###############################################################
#  Generated by:      Cadence Innovus 21.16-s078_1
#  OS:                Linux x86_64(Host ID iron-10)
#  Generated on:      Fri Feb 27 18:19:35 2026
#  Design:            conv
#  Command:           write_lef_abstract -specifyTopLayer 6 -PGPinLayers {5 6} -noCutObs -stripePin results/conv.lef
###############################################################

VERSION 5.8 ;

BUSBITCHARS "[]" ;
DIVIDERCHAR "/" ;

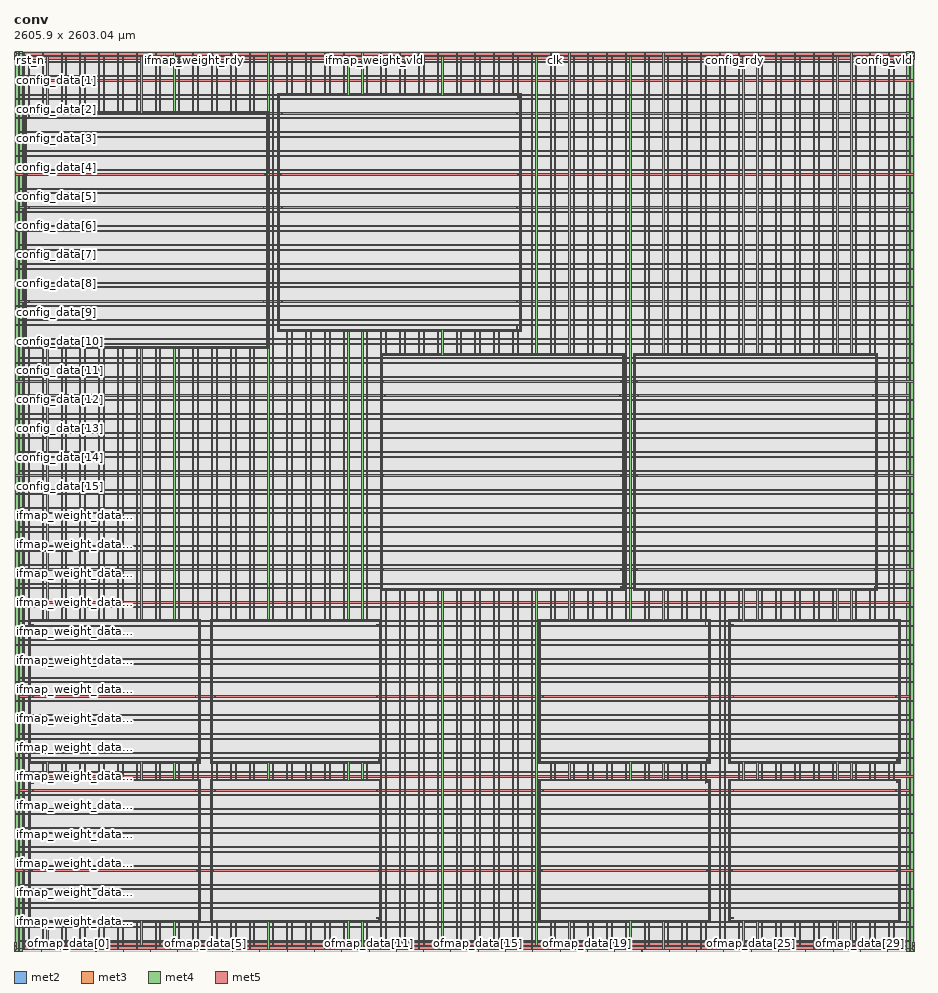
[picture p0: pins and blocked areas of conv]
MACRO conv
  CLASS BLOCK ;
  SIZE 2605.900000 BY 2603.040000 ;
  FOREIGN conv 0.000000 0.000000 ;
  ORIGIN 0 0 ;
  SYMMETRY X Y R90 ;
  PIN clk
    DIRECTION INPUT ;
    USE SIGNAL ;
    ANTENNAPARTIALMETALAREA 6.5113 LAYER met2  ;
    ANTENNAPARTIALMETALSIDEAREA 32.4485 LAYER met2  ;
    ANTENNAMODEL OXIDE1 ;
    ANTENNAGATEAREA 0.576 LAYER met2  ;
    ANTENNAMAXAREACAR 12.7497 LAYER met2  ;
    ANTENNAMAXSIDEAREACAR 61.5451 LAYER met2  ;
    ANTENNAMAXCUTCAR 0.0892361 LAYER via2  ;
    PORT
      LAYER met2 ;
        RECT 1563.240000 2602.555000 1563.380000 2603.040000 ;
    END
  END clk
  PIN rst_n
    DIRECTION INPUT ;
    USE SIGNAL ;
    ANTENNAPARTIALMETALAREA 9.5841 LAYER met2  ;
    ANTENNAPARTIALMETALSIDEAREA 47.6945 LAYER met2  ;
    ANTENNAMODEL OXIDE1 ;
    ANTENNAGATEAREA 0.576 LAYER met2  ;
    ANTENNAMAXAREACAR 34.4979 LAYER met2  ;
    ANTENNAMAXSIDEAREACAR 170.082 LAYER met2  ;
    ANTENNAMAXCUTCAR 0.0892361 LAYER via2  ;
    PORT
      LAYER met2 ;
        RECT 0.160000 2602.555000 0.300000 2603.040000 ;
    END
  END rst_n
  PIN ifmap_weight_data[16]
    DIRECTION INPUT ;
    USE SIGNAL ;
  END ifmap_weight_data[16]
  PIN ifmap_weight_data[15]
    DIRECTION INPUT ;
    USE SIGNAL ;
    ANTENNAPARTIALMETALAREA 6.3264 LAYER met3  ;
    ANTENNAPARTIALMETALSIDEAREA 33.736 LAYER met3  ;
    ANTENNAMODEL OXIDE1 ;
    ANTENNAGATEAREA 0.1965 LAYER met3  ;
    ANTENNAMAXAREACAR 37.8972 LAYER met3  ;
    ANTENNAMAXSIDEAREACAR 194.982 LAYER met3  ;
    ANTENNAMAXCUTCAR 0.46514 LAYER via3  ;
    PORT
      LAYER met3 ;
        RECT 0.000000 0.520000 0.800000 0.820000 ;
    END
  END ifmap_weight_data[15]
  PIN ifmap_weight_data[14]
    DIRECTION INPUT ;
    USE SIGNAL ;
    ANTENNAPARTIALMETALAREA 0.6954 LAYER met3  ;
    ANTENNAPARTIALMETALSIDEAREA 4.152 LAYER met3  ;
    ANTENNAPARTIALCUTAREA 0.04 LAYER via3  ;
    ANTENNADIFFAREA 0.4347 LAYER met4  ;
    ANTENNAPARTIALMETALAREA 6.1578 LAYER met4  ;
    ANTENNAPARTIALMETALSIDEAREA 33.312 LAYER met4  ;
    ANTENNAMODEL OXIDE1 ;
    ANTENNAGATEAREA 0.6312 LAYER met4  ;
    ANTENNAMAXAREACAR 117.866 LAYER met4  ;
    ANTENNAMAXSIDEAREACAR 579.27 LAYER met4  ;
    ANTENNAMAXCUTCAR 0.208175 LAYER via4  ;
    PORT
      LAYER met3 ;
        RECT 0.000000 84.090000 0.800000 84.390000 ;
    END
  END ifmap_weight_data[14]
  PIN ifmap_weight_data[13]
    DIRECTION INPUT ;
    USE SIGNAL ;
    ANTENNAPARTIALMETALAREA 6.6504 LAYER met3  ;
    ANTENNAPARTIALMETALSIDEAREA 35.464 LAYER met3  ;
    ANTENNAMODEL OXIDE1 ;
    ANTENNAGATEAREA 0.1965 LAYER met3  ;
    ANTENNAMAXAREACAR 59.1237 LAYER met3  ;
    ANTENNAMAXSIDEAREACAR 298.326 LAYER met3  ;
    ANTENNAMAXCUTCAR 0.46514 LAYER via3  ;
    PORT
      LAYER met3 ;
        RECT 0.000000 168.270000 0.800000 168.570000 ;
    END
  END ifmap_weight_data[13]
  PIN ifmap_weight_data[12]
    DIRECTION INPUT ;
    USE SIGNAL ;
    ANTENNAPARTIALMETALAREA 0.8644 LAYER met3  ;
    ANTENNAPARTIALMETALSIDEAREA 5.072 LAYER met3  ;
    ANTENNAPARTIALCUTAREA 0.04 LAYER via3  ;
    ANTENNAPARTIALMETALAREA 3.2298 LAYER met4  ;
    ANTENNAPARTIALMETALSIDEAREA 17.696 LAYER met4  ;
    ANTENNAMODEL OXIDE1 ;
    ANTENNAGATEAREA 0.498 LAYER met4  ;
    ANTENNAMAXAREACAR 21.4641 LAYER met4  ;
    ANTENNAMAXSIDEAREACAR 101.959 LAYER met4  ;
    ANTENNAMAXCUTCAR 0.435188 LAYER via4  ;
    PORT
      LAYER met3 ;
        RECT 0.000000 251.840000 0.800000 252.140000 ;
    END
  END ifmap_weight_data[12]
  PIN ifmap_weight_data[11]
    DIRECTION INPUT ;
    USE SIGNAL ;
    ANTENNADIFFAREA 0.4347 LAYER met3  ;
    ANTENNAPARTIALMETALAREA 6.0984 LAYER met3  ;
    ANTENNAPARTIALMETALSIDEAREA 32.52 LAYER met3  ;
    ANTENNAMODEL OXIDE1 ;
    ANTENNAGATEAREA 0.9327 LAYER met3  ;
    ANTENNAMAXAREACAR 119.127 LAYER met3  ;
    ANTENNAMAXSIDEAREACAR 587.966 LAYER met3  ;
    ANTENNAMAXCUTCAR 0.393219 LAYER via3  ;
    PORT
      LAYER met3 ;
        RECT 0.000000 336.020000 0.800000 336.320000 ;
    END
  END ifmap_weight_data[11]
  PIN ifmap_weight_data[10]
    DIRECTION INPUT ;
    USE SIGNAL ;
    ANTENNADIFFAREA 0.4347 LAYER met3  ;
    ANTENNAPARTIALMETALAREA 6.6504 LAYER met3  ;
    ANTENNAPARTIALMETALSIDEAREA 35.464 LAYER met3  ;
    ANTENNAMODEL OXIDE1 ;
    ANTENNAGATEAREA 0.9327 LAYER met3  ;
    ANTENNAMAXAREACAR 107.73 LAYER met3  ;
    ANTENNAMAXSIDEAREACAR 522.98 LAYER met3  ;
    ANTENNAMAXCUTCAR 0.337782 LAYER via3  ;
    PORT
      LAYER met3 ;
        RECT 0.000000 420.200000 0.800000 420.500000 ;
    END
  END ifmap_weight_data[10]
  PIN ifmap_weight_data[9]
    DIRECTION INPUT ;
    USE SIGNAL ;
    ANTENNADIFFAREA 0.4347 LAYER met3  ;
    ANTENNAPARTIALMETALAREA 7.0644 LAYER met3  ;
    ANTENNAPARTIALMETALSIDEAREA 37.672 LAYER met3  ;
    ANTENNAMODEL OXIDE1 ;
    ANTENNAGATEAREA 0.9327 LAYER met3  ;
    ANTENNAMAXAREACAR 92.4371 LAYER met3  ;
    ANTENNAMAXSIDEAREACAR 462.152 LAYER met3  ;
    ANTENNAMAXCUTCAR 0.450823 LAYER via3  ;
    PORT
      LAYER met3 ;
        RECT 0.000000 503.770000 0.800000 504.070000 ;
    END
  END ifmap_weight_data[9]
  PIN ifmap_weight_data[8]
    DIRECTION INPUT ;
    USE SIGNAL ;
    ANTENNAPARTIALMETALAREA 0.5574 LAYER met3  ;
    ANTENNAPARTIALMETALSIDEAREA 3.416 LAYER met3  ;
    ANTENNAPARTIALCUTAREA 0.04 LAYER via3  ;
    ANTENNAPARTIALMETALAREA 4.1448 LAYER met4  ;
    ANTENNAPARTIALMETALSIDEAREA 22.576 LAYER met4  ;
    ANTENNAMODEL OXIDE1 ;
    ANTENNAGATEAREA 0.498 LAYER met4  ;
    ANTENNAMAXAREACAR 34.5191 LAYER met4  ;
    ANTENNAMAXSIDEAREACAR 166.018 LAYER met4  ;
    ANTENNAMAXCUTCAR 0.74715 LAYER via4  ;
    PORT
      LAYER met3 ;
        RECT 0.000000 587.950000 0.800000 588.250000 ;
    END
  END ifmap_weight_data[8]
  PIN ifmap_weight_data[7]
    DIRECTION INPUT ;
    USE SIGNAL ;
    ANTENNAPARTIALMETALAREA 8.0053 LAYER met3  ;
    ANTENNAPARTIALMETALSIDEAREA 43.16 LAYER met3  ;
    ANTENNAPARTIALCUTAREA 0.04 LAYER via3  ;
    ANTENNAPARTIALMETALAREA 4.3518 LAYER met4  ;
    ANTENNAPARTIALMETALSIDEAREA 23.68 LAYER met4  ;
    ANTENNAMODEL OXIDE1 ;
    ANTENNAGATEAREA 0.498 LAYER met4  ;
    ANTENNAMAXAREACAR 36.3557 LAYER met4  ;
    ANTENNAMAXSIDEAREACAR 177.137 LAYER met4  ;
    ANTENNAMAXCUTCAR 0.435188 LAYER via4  ;
    PORT
      LAYER met3 ;
        RECT 0.000000 671.520000 0.800000 671.820000 ;
    END
  END ifmap_weight_data[7]
  PIN ifmap_weight_data[6]
    DIRECTION INPUT ;
    USE SIGNAL ;
    ANTENNAPARTIALMETALAREA 0.8544 LAYER met3  ;
    ANTENNAPARTIALMETALSIDEAREA 4.552 LAYER met3  ;
    ANTENNAMODEL OXIDE1 ;
    ANTENNAGATEAREA 0.498 LAYER met3  ;
    ANTENNAMAXAREACAR 110.536 LAYER met3  ;
    ANTENNAMAXSIDEAREACAR 542.113 LAYER met3  ;
    ANTENNAMAXCUTCAR 0.666829 LAYER via3  ;
    PORT
      LAYER met3 ;
        RECT 0.000000 755.700000 0.800000 756.000000 ;
    END
  END ifmap_weight_data[6]
  PIN ifmap_weight_data[5]
    DIRECTION INPUT ;
    USE SIGNAL ;
    ANTENNAPARTIALMETALAREA 13.596 LAYER met3  ;
    ANTENNAPARTIALMETALSIDEAREA 73.448 LAYER met3  ;
    ANTENNAMODEL OXIDE1 ;
    ANTENNAGATEAREA 0.498 LAYER met3  ;
    ANTENNAMAXAREACAR 51.1759 LAYER met3  ;
    ANTENNAMAXSIDEAREACAR 255.575 LAYER met3  ;
    ANTENNAMAXCUTCAR 0.801562 LAYER via3  ;
    PORT
      LAYER met3 ;
        RECT 0.000000 839.880000 0.800000 840.180000 ;
    END
  END ifmap_weight_data[5]
  PIN ifmap_weight_data[4]
    DIRECTION INPUT ;
    USE SIGNAL ;
    ANTENNAPARTIALMETALAREA 13.5504 LAYER met3  ;
    ANTENNAPARTIALMETALSIDEAREA 72.264 LAYER met3  ;
    ANTENNAMODEL OXIDE1 ;
    ANTENNAGATEAREA 0.498 LAYER met3  ;
    ANTENNAMAXAREACAR 65.7007 LAYER met3  ;
    ANTENNAMAXSIDEAREACAR 327.226 LAYER met3  ;
    ANTENNAMAXCUTCAR 0.488258 LAYER via3  ;
    PORT
      LAYER met3 ;
        RECT 0.000000 923.450000 0.800000 923.750000 ;
    END
  END ifmap_weight_data[4]
  PIN ifmap_weight_data[3]
    DIRECTION INPUT ;
    USE SIGNAL ;
    ANTENNAPARTIALMETALAREA 0.1644 LAYER met3  ;
    ANTENNAPARTIALMETALSIDEAREA 0.872 LAYER met3  ;
    ANTENNAMODEL OXIDE1 ;
    ANTENNAGATEAREA 0.498 LAYER met3  ;
    ANTENNAMAXAREACAR 35.9706 LAYER met3  ;
    ANTENNAMAXSIDEAREACAR 168.607 LAYER met3  ;
    ANTENNAMAXCUTCAR 0.666829 LAYER via3  ;
    PORT
      LAYER met3 ;
        RECT 0.000000 1007.630000 0.800000 1007.930000 ;
    END
  END ifmap_weight_data[3]
  PIN ifmap_weight_data[2]
    DIRECTION INPUT ;
    USE SIGNAL ;
    ANTENNAPARTIALMETALAREA 31.4904 LAYER met3  ;
    ANTENNAPARTIALMETALSIDEAREA 167.944 LAYER met3  ;
    ANTENNAMODEL OXIDE1 ;
    ANTENNAGATEAREA 0.498 LAYER met3  ;
    ANTENNAMAXAREACAR 88.3315 LAYER met3  ;
    ANTENNAMAXSIDEAREACAR 452.75 LAYER met3  ;
    ANTENNAMAXCUTCAR 0.398972 LAYER via3  ;
    PORT
      LAYER met3 ;
        RECT 0.000000 1091.200000 0.800000 1091.500000 ;
    END
  END ifmap_weight_data[2]
  PIN ifmap_weight_data[1]
    DIRECTION INPUT ;
    USE SIGNAL ;
    ANTENNAPARTIALMETALAREA 8.3064 LAYER met3  ;
    ANTENNAPARTIALMETALSIDEAREA 44.296 LAYER met3  ;
    ANTENNAMODEL OXIDE1 ;
    ANTENNAGATEAREA 0.498 LAYER met3  ;
    ANTENNAMAXAREACAR 75.0135 LAYER met3  ;
    ANTENNAMAXSIDEAREACAR 369.809 LAYER met3  ;
    ANTENNAMAXCUTCAR 0.666829 LAYER via3  ;
    PORT
      LAYER met3 ;
        RECT 0.000000 1175.380000 0.800000 1175.680000 ;
    END
  END ifmap_weight_data[1]
  PIN ifmap_weight_data[0]
    DIRECTION INPUT ;
    USE SIGNAL ;
    ANTENNAPARTIALMETALAREA 30.9384 LAYER met3  ;
    ANTENNAPARTIALMETALSIDEAREA 165 LAYER met3  ;
    ANTENNAMODEL OXIDE1 ;
    ANTENNAGATEAREA 0.498 LAYER met3  ;
    ANTENNAMAXAREACAR 142.031 LAYER met3  ;
    ANTENNAMAXSIDEAREACAR 720.859 LAYER met3  ;
    ANTENNAMAXCUTCAR 0.398972 LAYER via3  ;
    PORT
      LAYER met3 ;
        RECT 0.000000 1259.560000 0.800000 1259.860000 ;
    END
  END ifmap_weight_data[0]
  PIN ifmap_weight_rdy
    DIRECTION OUTPUT ;
    USE SIGNAL ;
    ANTENNADIFFAREA 0.43675 LAYER met2  ;
    ANTENNAPARTIALMETALAREA 32.4447 LAYER met2  ;
    ANTENNAPARTIALMETALSIDEAREA 161.997 LAYER met2  ;
    PORT
      LAYER met2 ;
        RECT 520.880000 2602.555000 521.020000 2603.040000 ;
    END
  END ifmap_weight_rdy
  PIN ifmap_weight_vld
    DIRECTION INPUT ;
    USE SIGNAL ;
    ANTENNAPARTIALMETALAREA 4.6507 LAYER met2  ;
    ANTENNAPARTIALMETALSIDEAREA 23.1455 LAYER met2  ;
    ANTENNAMODEL OXIDE1 ;
    ANTENNAGATEAREA 1.152 LAYER met2  ;
    ANTENNAMAXAREACAR 4.54191 LAYER met2  ;
    ANTENNAMAXSIDEAREACAR 20.8676 LAYER met2  ;
    ANTENNAMAXCUTCAR 0.0446181 LAYER via2  ;
    PORT
      LAYER met2 ;
        RECT 1042.060000 2602.555000 1042.200000 2603.040000 ;
    END
  END ifmap_weight_vld
  PIN ofmap_data[31]
    DIRECTION OUTPUT ;
    USE SIGNAL ;
    ANTENNADIFFAREA 0.3406 LAYER met2  ;
    ANTENNAPARTIALMETALAREA 10.1581 LAYER met2  ;
    ANTENNAPARTIALMETALSIDEAREA 50.5645 LAYER met2  ;
    PORT
      LAYER met2 ;
        RECT 2605.600000 0.000000 2605.740000 0.485000 ;
    END
  END ofmap_data[31]
  PIN ofmap_data[30]
    DIRECTION OUTPUT ;
    USE SIGNAL ;
    ANTENNADIFFAREA 0.3406 LAYER met2  ;
    ANTENNAPARTIALMETALAREA 10.2771 LAYER met2  ;
    ANTENNAPARTIALMETALSIDEAREA 51.1595 LAYER met2  ;
    PORT
      LAYER met2 ;
        RECT 2526.940000 0.000000 2527.080000 0.485000 ;
    END
  END ofmap_data[30]
  PIN ofmap_data[29]
    DIRECTION OUTPUT ;
    USE SIGNAL ;
    ANTENNADIFFAREA 0.3406 LAYER met2  ;
    ANTENNAPARTIALMETALAREA 10.2771 LAYER met2  ;
    ANTENNAPARTIALMETALSIDEAREA 51.1595 LAYER met2  ;
    PORT
      LAYER met2 ;
        RECT 2447.820000 0.000000 2447.960000 0.485000 ;
    END
  END ofmap_data[29]
  PIN ofmap_data[28]
    DIRECTION OUTPUT ;
    USE SIGNAL ;
    ANTENNADIFFAREA 0.3406 LAYER met2  ;
    ANTENNAPARTIALMETALAREA 5.4555 LAYER met2  ;
    ANTENNAPARTIALMETALSIDEAREA 27.0515 LAYER met2  ;
    PORT
      LAYER met2 ;
        RECT 2369.160000 0.000000 2369.300000 0.485000 ;
    END
  END ofmap_data[28]
  PIN ofmap_data[27]
    DIRECTION OUTPUT ;
    USE SIGNAL ;
    ANTENNADIFFAREA 0.3406 LAYER met2  ;
    ANTENNAPARTIALMETALAREA 7.9183 LAYER met2  ;
    ANTENNAPARTIALMETALSIDEAREA 39.4835 LAYER met2  ;
    PORT
      LAYER met2 ;
        RECT 2290.040000 0.000000 2290.180000 0.485000 ;
    END
  END ofmap_data[27]
  PIN ofmap_data[26]
    DIRECTION OUTPUT ;
    USE SIGNAL ;
    ANTENNADIFFAREA 0.3406 LAYER met2  ;
    ANTENNAPARTIALMETALAREA 4.2055 LAYER met2  ;
    ANTENNAPARTIALMETALSIDEAREA 20.9195 LAYER met2  ;
    PORT
      LAYER met2 ;
        RECT 2210.920000 0.000000 2211.060000 0.485000 ;
    END
  END ofmap_data[26]
  PIN ofmap_data[25]
    DIRECTION OUTPUT ;
    USE SIGNAL ;
    ANTENNADIFFAREA 0.3406 LAYER met2  ;
    ANTENNAPARTIALMETALAREA 4.8507 LAYER met2  ;
    ANTENNAPARTIALMETALSIDEAREA 24.0275 LAYER met2  ;
    PORT
      LAYER met2 ;
        RECT 2132.260000 0.000000 2132.400000 0.485000 ;
    END
  END ofmap_data[25]
  PIN ofmap_data[24]
    DIRECTION OUTPUT ;
    USE SIGNAL ;
    ANTENNADIFFAREA 0.3406 LAYER met2  ;
    ANTENNAPARTIALMETALAREA 4.1367 LAYER met2  ;
    ANTENNAPARTIALMETALSIDEAREA 20.4575 LAYER met2  ;
    PORT
      LAYER met2 ;
        RECT 2053.140000 0.000000 2053.280000 0.485000 ;
    END
  END ofmap_data[24]
  PIN ofmap_data[23]
    DIRECTION OUTPUT ;
    USE SIGNAL ;
    ANTENNADIFFAREA 0.3406 LAYER met2  ;
    ANTENNAPARTIALMETALAREA 8.5635 LAYER met2  ;
    ANTENNAPARTIALMETALSIDEAREA 42.5915 LAYER met2  ;
    PORT
      LAYER met2 ;
        RECT 1974.020000 0.000000 1974.160000 0.485000 ;
    END
  END ofmap_data[23]
  PIN ofmap_data[22]
    DIRECTION OUTPUT ;
    USE SIGNAL ;
    ANTENNADIFFAREA 0.3406 LAYER met2  ;
    ANTENNAPARTIALMETALAREA 10.2771 LAYER met2  ;
    ANTENNAPARTIALMETALSIDEAREA 51.1595 LAYER met2  ;
    PORT
      LAYER met2 ;
        RECT 1895.360000 0.000000 1895.500000 0.485000 ;
    END
  END ofmap_data[22]
  PIN ofmap_data[21]
    DIRECTION OUTPUT ;
    USE SIGNAL ;
    ANTENNADIFFAREA 0.3406 LAYER met2  ;
    ANTENNAPARTIALMETALAREA 11.4839 LAYER met2  ;
    ANTENNAPARTIALMETALSIDEAREA 57.1935 LAYER met2  ;
    PORT
      LAYER met2 ;
        RECT 1816.240000 0.000000 1816.380000 0.485000 ;
    END
  END ofmap_data[21]
  PIN ofmap_data[20]
    DIRECTION OUTPUT ;
    USE SIGNAL ;
    ANTENNADIFFAREA 0.429 LAYER met2  ;
    ANTENNAPARTIALMETALAREA 54.9119 LAYER met2  ;
    ANTENNAPARTIALMETALSIDEAREA 274.333 LAYER met2  ;
    PORT
      LAYER met2 ;
        RECT 1737.580000 0.000000 1737.720000 0.485000 ;
    END
  END ofmap_data[20]
  PIN ofmap_data[19]
    DIRECTION OUTPUT ;
    USE SIGNAL ;
    ANTENNADIFFAREA 0.429 LAYER met2  ;
    ANTENNAPARTIALMETALAREA 56.6871 LAYER met2  ;
    ANTENNAPARTIALMETALSIDEAREA 283.21 LAYER met2  ;
    PORT
      LAYER met2 ;
        RECT 1658.460000 0.000000 1658.600000 0.485000 ;
    END
  END ofmap_data[19]
  PIN ofmap_data[18]
    DIRECTION OUTPUT ;
    USE SIGNAL ;
    ANTENNADIFFAREA 0.429 LAYER met2  ;
    ANTENNAPARTIALMETALAREA 53.6407 LAYER met2  ;
    ANTENNAPARTIALMETALSIDEAREA 267.978 LAYER met2  ;
    PORT
      LAYER met2 ;
        RECT 1579.340000 0.000000 1579.480000 0.485000 ;
    END
  END ofmap_data[18]
  PIN ofmap_data[17]
    DIRECTION OUTPUT ;
    USE SIGNAL ;
    ANTENNADIFFAREA 0.429 LAYER met2  ;
    ANTENNAPARTIALMETALAREA 54.0383 LAYER met2  ;
    ANTENNAPARTIALMETALSIDEAREA 269.966 LAYER met2  ;
    PORT
      LAYER met2 ;
        RECT 1500.680000 0.000000 1500.820000 0.485000 ;
    END
  END ofmap_data[17]
  PIN ofmap_data[16]
    DIRECTION OUTPUT ;
    USE SIGNAL ;
    ANTENNADIFFAREA 0.429 LAYER met2  ;
    ANTENNAPARTIALMETALAREA 55.0239 LAYER met2  ;
    ANTENNAPARTIALMETALSIDEAREA 274.893 LAYER met2  ;
    PORT
      LAYER met2 ;
        RECT 1421.560000 0.000000 1421.700000 0.485000 ;
    END
  END ofmap_data[16]
  PIN ofmap_data[15]
    DIRECTION OUTPUT ;
    USE SIGNAL ;
    ANTENNADIFFAREA 0.429 LAYER met2  ;
    ANTENNAPARTIALMETALAREA 53.4239 LAYER met2  ;
    ANTENNAPARTIALMETALSIDEAREA 267.012 LAYER met2  ;
    PORT
      LAYER met2 ;
        RECT 1342.440000 0.000000 1342.580000 0.485000 ;
    END
  END ofmap_data[15]
  PIN ofmap_data[14]
    DIRECTION OUTPUT ;
    USE SIGNAL ;
    ANTENNADIFFAREA 0.429 LAYER met2  ;
    ANTENNAPARTIALMETALAREA 54.3479 LAYER met2  ;
    ANTENNAPARTIALMETALSIDEAREA 271.632 LAYER met2  ;
    PORT
      LAYER met2 ;
        RECT 1263.780000 0.000000 1263.920000 0.485000 ;
    END
  END ofmap_data[14]
  PIN ofmap_data[13]
    DIRECTION OUTPUT ;
    USE SIGNAL ;
    ANTENNADIFFAREA 0.429 LAYER met2  ;
    ANTENNAPARTIALMETALAREA 53.8311 LAYER met2  ;
    ANTENNAPARTIALMETALSIDEAREA 268.93 LAYER met2  ;
    PORT
      LAYER met2 ;
        RECT 1184.660000 0.000000 1184.800000 0.485000 ;
    END
  END ofmap_data[13]
  PIN ofmap_data[12]
    DIRECTION OUTPUT ;
    USE SIGNAL ;
    ANTENNADIFFAREA 0.429 LAYER met2  ;
    ANTENNAPARTIALMETALAREA 52.9267 LAYER met2  ;
    ANTENNAPARTIALMETALSIDEAREA 264.408 LAYER met2  ;
    PORT
      LAYER met2 ;
        RECT 1105.540000 0.000000 1105.680000 0.485000 ;
    END
  END ofmap_data[12]
  PIN ofmap_data[11]
    DIRECTION OUTPUT ;
    USE SIGNAL ;
    ANTENNADIFFAREA 0.429 LAYER met2  ;
    ANTENNAPARTIALMETALAREA 54.8307 LAYER met2  ;
    ANTENNAPARTIALMETALSIDEAREA 273.927 LAYER met2  ;
    PORT
      LAYER met2 ;
        RECT 1026.880000 0.000000 1027.020000 0.485000 ;
    END
  END ofmap_data[11]
  PIN ofmap_data[10]
    DIRECTION OUTPUT ;
    USE SIGNAL ;
    ANTENNADIFFAREA 0.429 LAYER met2  ;
    ANTENNAPARTIALMETALAREA 54.0215 LAYER met2  ;
    ANTENNAPARTIALMETALSIDEAREA 269.882 LAYER met2  ;
    PORT
      LAYER met2 ;
        RECT 947.760000 0.000000 947.900000 0.485000 ;
    END
  END ofmap_data[10]
  PIN ofmap_data[9]
    DIRECTION OUTPUT ;
    USE SIGNAL ;
    ANTENNADIFFAREA 0.3406 LAYER met2  ;
    ANTENNAPARTIALMETALAREA 10.7391 LAYER met2  ;
    ANTENNAPARTIALMETALSIDEAREA 53.4695 LAYER met2  ;
    PORT
      LAYER met2 ;
        RECT 869.100000 0.000000 869.240000 0.485000 ;
    END
  END ofmap_data[9]
  PIN ofmap_data[8]
    DIRECTION OUTPUT ;
    USE SIGNAL ;
    ANTENNADIFFAREA 0.3406 LAYER met2  ;
    ANTENNAPARTIALMETALAREA 10.6103 LAYER met2  ;
    ANTENNAPARTIALMETALSIDEAREA 52.8255 LAYER met2  ;
    PORT
      LAYER met2 ;
        RECT 789.980000 0.000000 790.120000 0.485000 ;
    END
  END ofmap_data[8]
  PIN ofmap_data[7]
    DIRECTION OUTPUT ;
    USE SIGNAL ;
    ANTENNADIFFAREA 0.3406 LAYER met2  ;
    ANTENNAPARTIALMETALAREA 10.9911 LAYER met2  ;
    ANTENNAPARTIALMETALSIDEAREA 54.7295 LAYER met2  ;
    PORT
      LAYER met2 ;
        RECT 710.860000 0.000000 711.000000 0.485000 ;
    END
  END ofmap_data[7]
  PIN ofmap_data[6]
    DIRECTION OUTPUT ;
    USE SIGNAL ;
    ANTENNADIFFAREA 0.3406 LAYER met2  ;
    ANTENNAPARTIALMETALAREA 9.8487 LAYER met2  ;
    ANTENNAPARTIALMETALSIDEAREA 49.0175 LAYER met2  ;
    PORT
      LAYER met2 ;
        RECT 632.200000 0.000000 632.340000 0.485000 ;
    END
  END ofmap_data[6]
  PIN ofmap_data[5]
    DIRECTION OUTPUT ;
    USE SIGNAL ;
    ANTENNADIFFAREA 0.3406 LAYER met2  ;
    ANTENNAPARTIALMETALAREA 7.5543 LAYER met2  ;
    ANTENNAPARTIALMETALSIDEAREA 37.6635 LAYER met2  ;
    PORT
      LAYER met2 ;
        RECT 553.080000 0.000000 553.220000 0.485000 ;
    END
  END ofmap_data[5]
  PIN ofmap_data[4]
    DIRECTION OUTPUT ;
    USE SIGNAL ;
    ANTENNADIFFAREA 0.3406 LAYER met2  ;
    ANTENNAPARTIALMETALAREA 4.0891 LAYER met2  ;
    ANTENNAPARTIALMETALSIDEAREA 20.2195 LAYER met2  ;
    PORT
      LAYER met2 ;
        RECT 473.960000 0.000000 474.100000 0.485000 ;
    END
  END ofmap_data[4]
  PIN ofmap_data[3]
    DIRECTION OUTPUT ;
    USE SIGNAL ;
    ANTENNADIFFAREA 0.3406 LAYER met2  ;
    ANTENNAPARTIALMETALAREA 4.2055 LAYER met2  ;
    ANTENNAPARTIALMETALSIDEAREA 20.9195 LAYER met2  ;
    PORT
      LAYER met2 ;
        RECT 395.300000 0.000000 395.440000 0.485000 ;
    END
  END ofmap_data[3]
  PIN ofmap_data[2]
    DIRECTION OUTPUT ;
    USE SIGNAL ;
    ANTENNADIFFAREA 0.3406 LAYER met2  ;
    ANTENNAPARTIALMETALAREA 7.7541 LAYER met2  ;
    ANTENNAPARTIALMETALSIDEAREA 38.4265 LAYER met2  ;
    PORT
      LAYER met2 ;
        RECT 316.180000 0.000000 316.320000 0.485000 ;
    END
  END ofmap_data[2]
  PIN ofmap_data[1]
    DIRECTION OUTPUT ;
    USE SIGNAL ;
    ANTENNADIFFAREA 0.3406 LAYER met2  ;
    ANTENNAPARTIALMETALAREA 7.8019 LAYER met2  ;
    ANTENNAPARTIALMETALSIDEAREA 38.7835 LAYER met2  ;
    PORT
      LAYER met2 ;
        RECT 237.060000 0.000000 237.200000 0.485000 ;
    END
  END ofmap_data[1]
  PIN ofmap_data[0]
    DIRECTION OUTPUT ;
    USE SIGNAL ;
    ANTENNADIFFAREA 0.3406 LAYER met2  ;
    ANTENNAPARTIALMETALAREA 8.3467 LAYER met2  ;
    ANTENNAPARTIALMETALSIDEAREA 41.6255 LAYER met2  ;
    PORT
      LAYER met2 ;
        RECT 158.400000 0.000000 158.540000 0.485000 ;
    END
  END ofmap_data[0]
  PIN ofmap_rdy
    DIRECTION INPUT ;
    USE SIGNAL ;
    ANTENNAPARTIALMETALAREA 9.4677 LAYER met2  ;
    ANTENNAPARTIALMETALSIDEAREA 46.9945 LAYER met2  ;
    ANTENNAMODEL OXIDE1 ;
    ANTENNAGATEAREA 0.126 LAYER met2  ;
    ANTENNAMAXAREACAR 96.4905 LAYER met2  ;
    ANTENNAMAXSIDEAREACAR 476.754 LAYER met2  ;
    ANTENNAMAXCUTCAR 0.407937 LAYER via2  ;
    PORT
      LAYER met2 ;
        RECT 0.160000 0.000000 0.300000 0.485000 ;
    END
  END ofmap_rdy
  PIN ofmap_vld
    DIRECTION OUTPUT ;
    USE SIGNAL ;
    ANTENNAPARTIALMETALAREA 7.1006 LAYER met2  ;
    ANTENNAPARTIALMETALSIDEAREA 35.224 LAYER met2  ;
    ANTENNAPARTIALCUTAREA 0.04 LAYER via2  ;
    ANTENNAPARTIALMETALAREA 0.2509 LAYER met3  ;
    ANTENNAPARTIALMETALSIDEAREA 1.808 LAYER met3  ;
    ANTENNAPARTIALCUTAREA 0.04 LAYER via3  ;
    ANTENNADIFFAREA 0.6626 LAYER met4  ;
    ANTENNAPARTIALMETALAREA 3.9618 LAYER met4  ;
    ANTENNAPARTIALMETALSIDEAREA 21.6 LAYER met4  ;
    ANTENNAMODEL OXIDE1 ;
    ANTENNAGATEAREA 0.126 LAYER met4  ;
    ANTENNAMAXAREACAR 149.892 LAYER met4  ;
    ANTENNAMAXSIDEAREACAR 779.754 LAYER met4  ;
    ANTENNAMAXCUTCAR 1.53889 LAYER via4  ;
    PORT
      LAYER met2 ;
        RECT 79.280000 0.000000 79.420000 0.485000 ;
    END
  END ofmap_vld
  PIN config_data[15]
    DIRECTION INPUT ;
    USE SIGNAL ;
    ANTENNAPARTIALMETALAREA 6.2113 LAYER met3  ;
    ANTENNAPARTIALMETALSIDEAREA 33.592 LAYER met3  ;
    ANTENNAPARTIALCUTAREA 0.04 LAYER via3  ;
    ANTENNAPARTIALMETALAREA 4.1448 LAYER met4  ;
    ANTENNAPARTIALMETALSIDEAREA 22.576 LAYER met4  ;
    ANTENNAMODEL OXIDE1 ;
    ANTENNAGATEAREA 0.498 LAYER met4  ;
    ANTENNAMAXAREACAR 22.007 LAYER met4  ;
    ANTENNAMAXSIDEAREACAR 108.54 LAYER met4  ;
    ANTENNAMAXCUTCAR 0.646988 LAYER via4  ;
    PORT
      LAYER met3 ;
        RECT 0.000000 1343.130000 0.800000 1343.430000 ;
    END
  END config_data[15]
  PIN config_data[14]
    DIRECTION INPUT ;
    USE SIGNAL ;
    ANTENNAPARTIALMETALAREA 30.6624 LAYER met3  ;
    ANTENNAPARTIALMETALSIDEAREA 163.528 LAYER met3  ;
    ANTENNAMODEL OXIDE1 ;
    ANTENNAGATEAREA 0.498 LAYER met3  ;
    ANTENNAMAXAREACAR 131.879 LAYER met3  ;
    ANTENNAMAXSIDEAREACAR 669.654 LAYER met3  ;
    ANTENNAMAXCUTCAR 0.488258 LAYER via3  ;
    PORT
      LAYER met3 ;
        RECT 0.000000 1427.310000 0.800000 1427.610000 ;
    END
  END config_data[14]
  PIN config_data[13]
    DIRECTION INPUT ;
    USE SIGNAL ;
    ANTENNAPARTIALMETALAREA 31.3974 LAYER met3  ;
    ANTENNAPARTIALMETALSIDEAREA 167.448 LAYER met3  ;
    ANTENNAMODEL OXIDE1 ;
    ANTENNAGATEAREA 0.498 LAYER met3  ;
    ANTENNAMAXAREACAR 112.107 LAYER met3  ;
    ANTENNAMAXSIDEAREACAR 571.203 LAYER met3  ;
    ANTENNAMAXCUTCAR 0.488258 LAYER via3  ;
    PORT
      LAYER met3 ;
        RECT 0.000000 1511.490000 0.800000 1511.790000 ;
    END
  END config_data[13]
  PIN config_data[12]
    DIRECTION INPUT ;
    USE SIGNAL ;
    ANTENNAPARTIALMETALAREA 0.1644 LAYER met3  ;
    ANTENNAPARTIALMETALSIDEAREA 0.872 LAYER met3  ;
    ANTENNAMODEL OXIDE1 ;
    ANTENNAGATEAREA 0.498 LAYER met3  ;
    ANTENNAMAXAREACAR 36.7041 LAYER met3  ;
    ANTENNAMAXSIDEAREACAR 171.397 LAYER met3  ;
    ANTENNAMAXCUTCAR 0.845401 LAYER via3  ;
    PORT
      LAYER met3 ;
        RECT 0.000000 1595.060000 0.800000 1595.360000 ;
    END
  END config_data[12]
  PIN config_data[11]
    DIRECTION INPUT ;
    USE SIGNAL ;
    ANTENNAPARTIALMETALAREA 58.2454 LAYER met3  ;
    ANTENNAPARTIALMETALSIDEAREA 311.104 LAYER met3  ;
    ANTENNAPARTIALCUTAREA 0.04 LAYER via3  ;
    ANTENNAPARTIALMETALAREA 0.6516 LAYER met4  ;
    ANTENNAPARTIALMETALSIDEAREA 4.416 LAYER met4  ;
    ANTENNAMODEL OXIDE1 ;
    ANTENNAGATEAREA 0.498 LAYER met4  ;
    ANTENNAMAXAREACAR 15.9219 LAYER met4  ;
    ANTENNAMAXSIDEAREACAR 74.0609 LAYER met4  ;
    ANTENNAMAXCUTCAR 0.568579 LAYER via4  ;
    PORT
      LAYER met3 ;
        RECT 0.000000 1679.240000 0.800000 1679.540000 ;
    END
  END config_data[11]
  PIN config_data[10]
    DIRECTION INPUT ;
    USE SIGNAL ;
    ANTENNAPARTIALMETALAREA 10.1004 LAYER met3  ;
    ANTENNAPARTIALMETALSIDEAREA 53.864 LAYER met3  ;
    ANTENNAMODEL OXIDE1 ;
    ANTENNAGATEAREA 0.498 LAYER met3  ;
    ANTENNAMAXAREACAR 66.0665 LAYER met3  ;
    ANTENNAMAXSIDEAREACAR 326.058 LAYER met3  ;
    ANTENNAMAXCUTCAR 0.666829 LAYER via3  ;
    PORT
      LAYER met3 ;
        RECT 0.000000 1762.810000 0.800000 1763.110000 ;
    END
  END config_data[10]
  PIN config_data[9]
    DIRECTION INPUT ;
    USE SIGNAL ;
    ANTENNAPARTIALMETALAREA 6.2364 LAYER met3  ;
    ANTENNAPARTIALMETALSIDEAREA 33.256 LAYER met3  ;
    ANTENNAMODEL OXIDE1 ;
    ANTENNAGATEAREA 0.498 LAYER met3  ;
    ANTENNAMAXAREACAR 87.6337 LAYER met3  ;
    ANTENNAMAXSIDEAREACAR 430.987 LAYER met3  ;
    ANTENNAMAXCUTCAR 0.666829 LAYER via3  ;
    PORT
      LAYER met3 ;
        RECT 0.000000 1846.990000 0.800000 1847.290000 ;
    END
  END config_data[9]
  PIN config_data[8]
    DIRECTION INPUT ;
    USE SIGNAL ;
    ANTENNAPARTIALMETALAREA 8.0304 LAYER met3  ;
    ANTENNAPARTIALMETALSIDEAREA 42.824 LAYER met3  ;
    ANTENNAMODEL OXIDE1 ;
    ANTENNAGATEAREA 0.498 LAYER met3  ;
    ANTENNAMAXAREACAR 113.967 LAYER met3  ;
    ANTENNAMAXSIDEAREACAR 563.379 LAYER met3  ;
    ANTENNAMAXCUTCAR 0.666829 LAYER via3  ;
    PORT
      LAYER met3 ;
        RECT 0.000000 1931.170000 0.800000 1931.470000 ;
    END
  END config_data[8]
  PIN config_data[7]
    DIRECTION INPUT ;
    USE SIGNAL ;
    ANTENNAPARTIALMETALAREA 9.8034 LAYER met3  ;
    ANTENNAPARTIALMETALSIDEAREA 52.728 LAYER met3  ;
    ANTENNAPARTIALCUTAREA 0.04 LAYER via3  ;
    ANTENNAPARTIALMETALAREA 4.1448 LAYER met4  ;
    ANTENNAPARTIALMETALSIDEAREA 22.576 LAYER met4  ;
    ANTENNAMODEL OXIDE1 ;
    ANTENNAGATEAREA 0.498 LAYER met4  ;
    ANTENNAMAXAREACAR 26.704 LAYER met4  ;
    ANTENNAMAXSIDEAREACAR 127.2 LAYER met4  ;
    ANTENNAMAXCUTCAR 0.74715 LAYER via4  ;
    PORT
      LAYER met3 ;
        RECT 0.000000 2014.740000 0.800000 2015.040000 ;
    END
  END config_data[7]
  PIN config_data[6]
    DIRECTION INPUT ;
    USE SIGNAL ;
    ANTENNAPARTIALMETALAREA 9.618 LAYER met3  ;
    ANTENNAPARTIALMETALSIDEAREA 52.232 LAYER met3  ;
    ANTENNAMODEL OXIDE1 ;
    ANTENNAGATEAREA 0.498 LAYER met3  ;
    ANTENNAMAXAREACAR 106.306 LAYER met3  ;
    ANTENNAMAXSIDEAREACAR 528.737 LAYER met3  ;
    ANTENNAMAXCUTCAR 0.666829 LAYER via3  ;
    PORT
      LAYER met3 ;
        RECT 0.000000 2098.920000 0.800000 2099.220000 ;
    END
  END config_data[6]
  PIN config_data[5]
    DIRECTION INPUT ;
    USE SIGNAL ;
    ANTENNAPARTIALMETALAREA 8.0053 LAYER met3  ;
    ANTENNAPARTIALMETALSIDEAREA 43.16 LAYER met3  ;
    ANTENNAPARTIALCUTAREA 0.04 LAYER via3  ;
    ANTENNAPARTIALMETALAREA 4.3518 LAYER met4  ;
    ANTENNAPARTIALMETALSIDEAREA 23.68 LAYER met4  ;
    ANTENNAMODEL OXIDE1 ;
    ANTENNAGATEAREA 0.498 LAYER met4  ;
    ANTENNAMAXAREACAR 33.9743 LAYER met4  ;
    ANTENNAMAXSIDEAREACAR 164.154 LAYER met4  ;
    ANTENNAMAXCUTCAR 0.568579 LAYER via4  ;
    PORT
      LAYER met3 ;
        RECT 0.000000 2182.490000 0.800000 2182.790000 ;
    END
  END config_data[5]
  PIN config_data[4]
    DIRECTION INPUT ;
    USE SIGNAL ;
    ANTENNADIFFAREA 0.4347 LAYER met3  ;
    ANTENNAPARTIALMETALAREA 7.0644 LAYER met3  ;
    ANTENNAPARTIALMETALSIDEAREA 37.672 LAYER met3  ;
    ANTENNAMODEL OXIDE1 ;
    ANTENNAGATEAREA 0.9327 LAYER met3  ;
    ANTENNAMAXAREACAR 117.194 LAYER met3  ;
    ANTENNAMAXSIDEAREACAR 577.734 LAYER met3  ;
    ANTENNAMAXCUTCAR 0.629394 LAYER via3  ;
    PORT
      LAYER met3 ;
        RECT 0.000000 2266.670000 0.800000 2266.970000 ;
    END
  END config_data[4]
  PIN config_data[3]
    DIRECTION INPUT ;
    USE SIGNAL ;
    ANTENNADIFFAREA 0.4347 LAYER met3  ;
    ANTENNAPARTIALMETALAREA 7.4044 LAYER met3  ;
    ANTENNAPARTIALMETALSIDEAREA 39.952 LAYER met3  ;
    ANTENNAMODEL OXIDE1 ;
    ANTENNAGATEAREA 0.5607 LAYER met3  ;
    ANTENNAMAXAREACAR 186.831 LAYER met3  ;
    ANTENNAMAXSIDEAREACAR 927.083 LAYER met3  ;
    ANTENNAPARTIALCUTAREA 0.04 LAYER via3  ;
    ANTENNAMAXCUTCAR 0.621955 LAYER via3  ;
    ANTENNADIFFAREA 0.4347 LAYER met4  ;
    ANTENNAPARTIALMETALAREA 1.9488 LAYER met4  ;
    ANTENNAPARTIALMETALSIDEAREA 10.864 LAYER met4  ;
    ANTENNAGATEAREA 0.9327 LAYER met4  ;
    ANTENNAMAXAREACAR 188.92 LAYER met4  ;
    ANTENNAMAXSIDEAREACAR 938.73 LAYER met4  ;
    ANTENNAMAXCUTCAR 0.621955 LAYER via4  ;
    PORT
      LAYER met3 ;
        RECT 0.000000 2350.850000 0.800000 2351.150000 ;
    END
  END config_data[3]
  PIN config_data[2]
    DIRECTION INPUT ;
    USE SIGNAL ;
    ANTENNAPARTIALMETALAREA 6.2113 LAYER met3  ;
    ANTENNAPARTIALMETALSIDEAREA 33.592 LAYER met3  ;
    ANTENNAPARTIALCUTAREA 0.04 LAYER via3  ;
    ANTENNAPARTIALMETALAREA 6.1578 LAYER met4  ;
    ANTENNAPARTIALMETALSIDEAREA 33.312 LAYER met4  ;
    ANTENNAMODEL OXIDE1 ;
    ANTENNAGATEAREA 0.498 LAYER met4  ;
    ANTENNAMAXAREACAR 21.7369 LAYER met4  ;
    ANTENNAMAXSIDEAREACAR 104.311 LAYER met4  ;
    ANTENNAMAXCUTCAR 0.74715 LAYER via4  ;
    PORT
      LAYER met3 ;
        RECT 0.000000 2434.420000 0.800000 2434.720000 ;
    END
  END config_data[2]
  PIN config_data[1]
    DIRECTION INPUT ;
    USE SIGNAL ;
    ANTENNAPARTIALMETALAREA 8.5824 LAYER met3  ;
    ANTENNAPARTIALMETALSIDEAREA 45.768 LAYER met3  ;
    ANTENNAMODEL OXIDE1 ;
    ANTENNAGATEAREA 1.485 LAYER met3  ;
    ANTENNAMAXAREACAR 6.34788 LAYER met3  ;
    ANTENNAMAXSIDEAREACAR 31.8259 LAYER met3  ;
    ANTENNAMAXCUTCAR 0.0615488 LAYER via3  ;
    PORT
      LAYER met3 ;
        RECT 0.000000 2518.600000 0.800000 2518.900000 ;
    END
  END config_data[1]
  PIN config_data[0]
    DIRECTION INPUT ;
    USE SIGNAL ;
    ANTENNAPARTIALMETALAREA 6.3264 LAYER met3  ;
    ANTENNAPARTIALMETALSIDEAREA 33.736 LAYER met3  ;
    ANTENNAMODEL OXIDE1 ;
    ANTENNAGATEAREA 0.1965 LAYER met3  ;
    ANTENNAMAXAREACAR 39.4514 LAYER met3  ;
    ANTENNAMAXSIDEAREACAR 198.69 LAYER met3  ;
    ANTENNAMAXCUTCAR 0.46514 LAYER via3  ;
    PORT
      LAYER met3 ;
        RECT 0.000000 2602.170000 0.800000 2602.470000 ;
    END
  END config_data[0]
  PIN config_rdy
    DIRECTION OUTPUT ;
    USE SIGNAL ;
    ANTENNADIFFAREA 0.3406 LAYER met2  ;
    ANTENNAPARTIALMETALAREA 68.1799 LAYER met2  ;
    ANTENNAPARTIALMETALSIDEAREA 340.791 LAYER met2  ;
    PORT
      LAYER met2 ;
        RECT 2084.420000 2602.555000 2084.560000 2603.040000 ;
    END
  END config_rdy
  PIN config_vld
    DIRECTION INPUT ;
    USE SIGNAL ;
    ANTENNAPARTIALMETALAREA 108.673 LAYER met2  ;
    ANTENNAPARTIALMETALSIDEAREA 543.088 LAYER met2  ;
    ANTENNAPARTIALCUTAREA 0.04 LAYER via2  ;
    ANTENNAPARTIALMETALAREA 0.331 LAYER met3  ;
    ANTENNAPARTIALMETALSIDEAREA 2.232 LAYER met3  ;
    ANTENNAPARTIALCUTAREA 0.04 LAYER via3  ;
    ANTENNAPARTIALMETALAREA 9.3648 LAYER met4  ;
    ANTENNAPARTIALMETALSIDEAREA 50.416 LAYER met4  ;
    ANTENNAMODEL OXIDE1 ;
    ANTENNAGATEAREA 0.1965 LAYER met4  ;
    ANTENNAMAXAREACAR 103.296 LAYER met4  ;
    ANTENNAMAXSIDEAREACAR 534.036 LAYER met4  ;
    ANTENNAMAXCUTCAR 0.668702 LAYER via4  ;
    PORT
      LAYER met2 ;
        RECT 2605.600000 2602.555000 2605.740000 2603.040000 ;
    END
  END config_vld
  PIN VSS
    DIRECTION INOUT ;
    USE GROUND ;
    PORT
      LAYER met4 ;
        RECT 2593.240000 2594.880000 2601.400000 2603.040000 ;
    END
    PORT
      LAYER met4 ;
        RECT 2593.240000 0.000000 2601.400000 8.160000 ;
    END
    PORT
      LAYER met4 ;
        RECT 4.500000 2594.880000 12.660000 2603.040000 ;
    END
    PORT
      LAYER met4 ;
        RECT 4.500000 0.000000 12.660000 8.160000 ;
    END
    PORT
      LAYER met5 ;
        RECT 2597.740000 2590.800000 2605.900000 2598.960000 ;
    END
    PORT
      LAYER met5 ;
        RECT 0.000000 2590.800000 8.160000 2598.960000 ;
    END
    PORT
      LAYER met5 ;
        RECT 2597.740000 4.080000 2605.900000 12.240000 ;
    END
    PORT
      LAYER met5 ;
        RECT 0.000000 4.080000 8.160000 12.240000 ;
    END

# P/G power stripe data as pin
    PORT
      LAYER met4 ;
        RECT 27.200000 4.080000 30.560000 2598.960000 ;
        RECT 571.200000 954.220000 574.560000 1744.600000 ;
        RECT 625.600000 955.620000 628.960000 1744.600000 ;
        RECT 516.800000 955.620000 520.160000 1744.600000 ;
        RECT 462.400000 955.620000 465.760000 1744.600000 ;
        RECT 408.000000 955.620000 411.360000 1744.600000 ;
        RECT 353.600000 955.620000 356.960000 1744.600000 ;
        RECT 299.200000 955.620000 302.560000 1744.600000 ;
        RECT 244.800000 955.620000 248.160000 1744.600000 ;
        RECT 190.400000 955.620000 193.760000 1744.600000 ;
        RECT 136.000000 955.620000 139.360000 1744.600000 ;
        RECT 81.600000 955.620000 84.960000 1744.600000 ;
        RECT 4.500000 0.000000 12.660000 2603.040000 ;
        RECT 1059.800000 1042.800000 1061.600000 1728.740000 ;
        RECT 734.400000 955.620000 737.760000 2598.960000 ;
        RECT 1006.400000 955.620000 1009.760000 1794.600000 ;
        RECT 952.000000 955.620000 955.360000 1794.600000 ;
        RECT 897.600000 955.620000 900.960000 1794.600000 ;
        RECT 843.200000 955.620000 846.560000 1794.600000 ;
        RECT 788.800000 955.620000 792.160000 1794.600000 ;
        RECT 680.000000 955.620000 683.360000 1744.600000 ;
        RECT 2593.240000 0.000000 2601.400000 2603.040000 ;
        RECT 1768.000000 955.620000 1771.360000 2598.960000 ;
        RECT 2529.600000 955.620000 2532.960000 2598.960000 ;
        RECT 1762.980000 1042.800000 1764.780000 1728.740000 ;
        RECT 1792.800000 1042.800000 1794.600000 1728.740000 ;
        RECT 2495.980000 1042.800000 2497.780000 1728.740000 ;
        RECT 1061.540000 542.800000 1063.340000 957.420000 ;
        RECT 567.800000 542.800000 569.600000 957.420000 ;
        RECT 536.540000 542.800000 538.340000 957.420000 ;
        RECT 42.800000 542.800000 44.600000 957.420000 ;
        RECT 1060.800000 4.080000 1064.160000 1046.000000 ;
        RECT 1278.400000 4.080000 1281.760000 1044.600000 ;
        RECT 1224.000000 4.080000 1227.360000 1044.600000 ;
        RECT 1169.600000 4.080000 1172.960000 1044.600000 ;
        RECT 1115.200000 4.080000 1118.560000 1044.600000 ;
        RECT 567.800000 82.800000 569.600000 497.420000 ;
        RECT 536.540000 82.800000 538.340000 497.420000 ;
        RECT 42.800000 82.800000 44.600000 497.420000 ;
        RECT 136.000000 4.080000 139.360000 84.600000 ;
        RECT 81.600000 4.080000 84.960000 84.600000 ;
        RECT 299.200000 4.080000 302.560000 84.600000 ;
        RECT 244.800000 4.080000 248.160000 84.600000 ;
        RECT 190.400000 4.080000 193.760000 84.600000 ;
        RECT 571.200000 4.080000 574.560000 86.000000 ;
        RECT 625.600000 4.080000 628.960000 84.600000 ;
        RECT 516.800000 4.080000 520.160000 84.600000 ;
        RECT 462.400000 4.080000 465.760000 84.600000 ;
        RECT 408.000000 4.080000 411.360000 84.600000 ;
        RECT 353.600000 4.080000 356.960000 84.600000 ;
        RECT 81.600000 495.620000 84.960000 544.600000 ;
        RECT 571.200000 494.220000 574.560000 546.000000 ;
        RECT 1061.540000 82.800000 1063.340000 497.420000 ;
        RECT 952.000000 4.080000 955.360000 84.600000 ;
        RECT 897.600000 4.080000 900.960000 84.600000 ;
        RECT 843.200000 4.080000 846.560000 84.600000 ;
        RECT 788.800000 4.080000 792.160000 84.600000 ;
        RECT 680.000000 4.080000 683.360000 84.600000 ;
        RECT 734.400000 4.080000 737.760000 84.600000 ;
        RECT 1006.400000 4.080000 1009.760000 84.600000 ;
        RECT 2561.540000 542.800000 2563.340000 957.420000 ;
        RECT 2067.800000 542.800000 2069.600000 957.420000 ;
        RECT 2011.540000 542.800000 2013.340000 957.420000 ;
        RECT 1517.800000 542.800000 1519.600000 957.420000 ;
        RECT 2040.000000 4.080000 2043.360000 1044.600000 ;
        RECT 1496.000000 4.080000 1499.360000 1044.600000 ;
        RECT 1441.600000 4.080000 1444.960000 1044.600000 ;
        RECT 1387.200000 4.080000 1390.560000 1044.600000 ;
        RECT 1332.800000 4.080000 1336.160000 1044.600000 ;
        RECT 1517.800000 82.800000 1519.600000 497.420000 ;
        RECT 1931.200000 4.080000 1934.560000 84.600000 ;
        RECT 1550.400000 4.080000 1553.760000 84.600000 ;
        RECT 1604.800000 4.080000 1608.160000 84.600000 ;
        RECT 1659.200000 4.080000 1662.560000 84.600000 ;
        RECT 1713.600000 4.080000 1716.960000 84.600000 ;
        RECT 1768.000000 4.080000 1771.360000 84.600000 ;
        RECT 1822.400000 4.080000 1825.760000 84.600000 ;
        RECT 1876.800000 4.080000 1880.160000 84.600000 ;
        RECT 2561.540000 82.800000 2563.340000 497.420000 ;
        RECT 2067.800000 82.800000 2069.600000 497.420000 ;
        RECT 2011.540000 82.800000 2013.340000 497.420000 ;
        RECT 2529.600000 4.080000 2532.960000 84.600000 ;
        RECT 2475.200000 4.080000 2478.560000 84.600000 ;
        RECT 2420.800000 4.080000 2424.160000 84.600000 ;
        RECT 2366.400000 4.080000 2369.760000 84.600000 ;
        RECT 2312.000000 4.080000 2315.360000 84.600000 ;
        RECT 2257.600000 4.080000 2260.960000 84.600000 ;
        RECT 2203.200000 4.080000 2206.560000 84.600000 ;
        RECT 2148.800000 4.080000 2152.160000 84.600000 ;
        RECT 2094.400000 4.080000 2097.760000 84.600000 ;
        RECT 1985.600000 4.080000 1988.960000 84.600000 ;
        RECT 1550.400000 955.620000 1553.760000 1044.600000 ;
        RECT 1604.800000 955.620000 1608.160000 1044.600000 ;
        RECT 1659.200000 955.620000 1662.560000 1044.600000 ;
        RECT 1713.600000 955.620000 1716.960000 1044.600000 ;
        RECT 1822.400000 955.620000 1825.760000 1044.600000 ;
        RECT 1876.800000 955.620000 1880.160000 1044.600000 ;
        RECT 1931.200000 955.620000 1934.560000 1044.600000 ;
        RECT 1985.600000 955.620000 1988.960000 1044.600000 ;
        RECT 2094.400000 955.620000 2097.760000 1044.600000 ;
        RECT 2148.800000 955.620000 2152.160000 1044.600000 ;
        RECT 2203.200000 955.620000 2206.560000 1044.600000 ;
        RECT 2257.600000 955.620000 2260.960000 1044.600000 ;
        RECT 2312.000000 955.620000 2315.360000 1044.600000 ;
        RECT 2366.400000 955.620000 2369.760000 1044.600000 ;
        RECT 2420.800000 955.620000 2424.160000 1044.600000 ;
        RECT 2475.200000 955.620000 2478.560000 1044.600000 ;
        RECT 762.800000 1792.800000 764.600000 2478.740000 ;
        RECT 732.980000 1742.800000 734.780000 2428.740000 ;
        RECT 29.800000 1742.800000 31.600000 2428.740000 ;
        RECT 38.360000 1752.400000 40.100000 1754.700000 ;
        RECT 38.360000 1752.230000 40.100000 1753.550000 ;
        RECT 1115.200000 1726.940000 1118.560000 1794.600000 ;
        RECT 1060.800000 1725.540000 1064.160000 1794.600000 ;
        RECT 299.200000 2426.940000 302.560000 2598.960000 ;
        RECT 244.800000 2426.940000 248.160000 2598.960000 ;
        RECT 190.400000 2426.940000 193.760000 2598.960000 ;
        RECT 136.000000 2426.940000 139.360000 2598.960000 ;
        RECT 81.600000 2426.940000 84.960000 2598.960000 ;
        RECT 625.600000 2426.940000 628.960000 2598.960000 ;
        RECT 571.200000 2426.940000 574.560000 2598.960000 ;
        RECT 516.800000 2426.940000 520.160000 2598.960000 ;
        RECT 462.400000 2426.940000 465.760000 2598.960000 ;
        RECT 408.000000 2426.940000 411.360000 2598.960000 ;
        RECT 353.600000 2426.940000 356.960000 2598.960000 ;
        RECT 788.800000 2476.940000 792.160000 2598.960000 ;
        RECT 843.200000 2476.940000 846.560000 2598.960000 ;
        RECT 897.600000 2476.940000 900.960000 2598.960000 ;
        RECT 952.000000 2476.940000 955.360000 2598.960000 ;
        RECT 1006.400000 2476.940000 1009.760000 2598.960000 ;
        RECT 1060.800000 2476.940000 1064.160000 2598.960000 ;
        RECT 1115.200000 2476.940000 1118.560000 2598.960000 ;
        RECT 1169.600000 2476.940000 1172.960000 2598.960000 ;
        RECT 1224.000000 2476.940000 1227.360000 2598.960000 ;
        RECT 1278.400000 2476.940000 1281.760000 2598.960000 ;
        RECT 680.000000 2426.940000 683.360000 2598.960000 ;
        RECT 1496.000000 1726.940000 1499.360000 2598.960000 ;
        RECT 1550.400000 1726.940000 1553.760000 2598.960000 ;
        RECT 1604.800000 1726.940000 1608.160000 2598.960000 ;
        RECT 1659.200000 1726.940000 1662.560000 2598.960000 ;
        RECT 1713.600000 1726.940000 1716.960000 2598.960000 ;
        RECT 1822.400000 1726.940000 1825.760000 2598.960000 ;
        RECT 1876.800000 1726.940000 1880.160000 2598.960000 ;
        RECT 1931.200000 1726.940000 1934.560000 2598.960000 ;
        RECT 1465.980000 1792.800000 1467.780000 2478.740000 ;
        RECT 1985.600000 1726.940000 1988.960000 2598.960000 ;
        RECT 2040.000000 1726.940000 2043.360000 2598.960000 ;
        RECT 2094.400000 1726.940000 2097.760000 2598.960000 ;
        RECT 2148.800000 1726.940000 2152.160000 2598.960000 ;
        RECT 2203.200000 1726.940000 2206.560000 2598.960000 ;
        RECT 2257.600000 1726.940000 2260.960000 2598.960000 ;
        RECT 2312.000000 1726.940000 2315.360000 2598.960000 ;
        RECT 2366.400000 1726.940000 2369.760000 2598.960000 ;
        RECT 2420.800000 1726.940000 2424.160000 2598.960000 ;
        RECT 2475.200000 1726.940000 2478.560000 2598.960000 ;
        RECT 1332.800000 2476.940000 1336.160000 2598.960000 ;
        RECT 1387.200000 2476.940000 1390.560000 2598.960000 ;
        RECT 1441.600000 2476.940000 1444.960000 2598.960000 ;
        RECT 625.600000 495.620000 628.960000 544.600000 ;
        RECT 680.000000 495.620000 683.360000 544.600000 ;
        RECT 734.400000 495.620000 737.760000 544.600000 ;
        RECT 788.800000 495.620000 792.160000 544.600000 ;
        RECT 843.200000 495.620000 846.560000 544.600000 ;
        RECT 897.600000 495.620000 900.960000 544.600000 ;
        RECT 952.000000 495.620000 955.360000 544.600000 ;
        RECT 1006.400000 495.620000 1009.760000 544.600000 ;
        RECT 136.000000 495.620000 139.360000 544.600000 ;
        RECT 190.400000 495.620000 193.760000 544.600000 ;
        RECT 244.800000 495.620000 248.160000 544.600000 ;
        RECT 299.200000 495.620000 302.560000 544.600000 ;
        RECT 353.600000 495.620000 356.960000 544.600000 ;
        RECT 408.000000 495.620000 411.360000 544.600000 ;
        RECT 462.400000 495.620000 465.760000 544.600000 ;
        RECT 516.800000 495.620000 520.160000 544.600000 ;
        RECT 1550.400000 495.620000 1553.760000 544.600000 ;
        RECT 1604.800000 495.620000 1608.160000 544.600000 ;
        RECT 1659.200000 495.620000 1662.560000 544.600000 ;
        RECT 1713.600000 495.620000 1716.960000 544.600000 ;
        RECT 1768.000000 495.620000 1771.360000 544.600000 ;
        RECT 1822.400000 495.620000 1825.760000 544.600000 ;
        RECT 1876.800000 495.620000 1880.160000 544.600000 ;
        RECT 1931.200000 495.620000 1934.560000 544.600000 ;
        RECT 1985.600000 495.620000 1988.960000 544.600000 ;
        RECT 2094.400000 495.620000 2097.760000 544.600000 ;
        RECT 2148.800000 495.620000 2152.160000 544.600000 ;
        RECT 2203.200000 495.620000 2206.560000 544.600000 ;
        RECT 2257.600000 495.620000 2260.960000 544.600000 ;
        RECT 2312.000000 495.620000 2315.360000 544.600000 ;
        RECT 2366.400000 495.620000 2369.760000 544.600000 ;
        RECT 2420.800000 495.620000 2424.160000 544.600000 ;
        RECT 2475.200000 495.620000 2478.560000 544.600000 ;
        RECT 2529.600000 495.620000 2532.960000 544.600000 ;
        RECT 1169.600000 1726.940000 1172.960000 1794.600000 ;
        RECT 1224.000000 1726.940000 1227.360000 1794.600000 ;
        RECT 1278.400000 1726.940000 1281.760000 1794.600000 ;
        RECT 1332.800000 1726.940000 1336.160000 1794.600000 ;
        RECT 1387.200000 1726.940000 1390.560000 1794.600000 ;
        RECT 1441.600000 1726.940000 1444.960000 1794.600000 ;
        RECT 51.360000 91.360000 53.100000 93.100000 ;
        RECT 528.040000 551.360000 529.780000 553.100000 ;
        RECT 1053.040000 91.360000 1054.780000 93.100000 ;
        RECT 1053.040000 551.360000 1054.780000 553.100000 ;
        RECT 1059.800000 1042.800000 1064.160000 1044.600000 ;
        RECT 2003.040000 487.120000 2004.780000 488.860000 ;
        RECT 2003.040000 551.360000 2004.780000 553.100000 ;
        RECT 2553.040000 487.120000 2554.780000 488.860000 ;
        RECT 2553.040000 551.360000 2554.780000 553.100000 ;
        RECT 1754.790000 1051.360000 1756.210000 1053.100000 ;
        RECT 1757.500000 1051.360000 1758.920000 1053.100000 ;
        RECT 2487.790000 1051.360000 2489.210000 1053.100000 ;
        RECT 2490.500000 1051.360000 2491.920000 1053.100000 ;
        RECT 38.360000 1808.800000 40.100000 1812.160000 ;
        RECT 27.200000 1754.400000 31.600000 1757.760000 ;
        RECT 38.360000 1752.400000 40.100000 1757.760000 ;
        RECT 1059.800000 1726.940000 1064.160000 1728.740000 ;
        RECT 732.980000 1754.400000 737.760000 1757.760000 ;
        RECT 1457.480000 2468.440000 1459.220000 2470.180000 ;
        RECT 1068.360000 1101.600000 1070.100000 1104.960000 ;
        RECT 1068.360000 1156.000000 1070.100000 1159.360000 ;
        RECT 1068.360000 1210.400000 1070.100000 1213.760000 ;
        RECT 1068.360000 1264.800000 1070.100000 1268.160000 ;
        RECT 1068.360000 1319.200000 1070.100000 1322.560000 ;
        RECT 1068.360000 1373.600000 1070.100000 1376.960000 ;
        RECT 1068.360000 1428.000000 1070.100000 1431.360000 ;
        RECT 1068.360000 1482.400000 1070.100000 1485.760000 ;
        RECT 1068.360000 1536.800000 1070.100000 1540.160000 ;
        RECT 1068.360000 1591.200000 1070.100000 1594.560000 ;
        RECT 1068.360000 1645.600000 1070.100000 1648.960000 ;
        RECT 1068.360000 1700.000000 1070.100000 1703.360000 ;
        RECT 2487.480000 1101.600000 2489.220000 1104.960000 ;
        RECT 2487.480000 1156.000000 2489.220000 1159.360000 ;
        RECT 2487.480000 1210.400000 2489.220000 1213.760000 ;
        RECT 2487.480000 1264.800000 2489.220000 1268.160000 ;
        RECT 2487.480000 1319.200000 2489.220000 1322.560000 ;
        RECT 2487.480000 1373.600000 2489.220000 1376.960000 ;
        RECT 2487.480000 1428.000000 2489.220000 1431.360000 ;
        RECT 2487.480000 1482.400000 2489.220000 1485.760000 ;
        RECT 2487.480000 1536.800000 2489.220000 1540.160000 ;
        RECT 2487.480000 1591.200000 2489.220000 1594.560000 ;
        RECT 2487.480000 1645.600000 2489.220000 1648.960000 ;
        RECT 2487.480000 1700.000000 2489.220000 1703.360000 ;
        RECT 1801.360000 1101.600000 1803.100000 1104.960000 ;
        RECT 1801.360000 1156.000000 1803.100000 1159.360000 ;
        RECT 1801.360000 1210.400000 1803.100000 1213.760000 ;
        RECT 1801.360000 1264.800000 1803.100000 1268.160000 ;
        RECT 1801.360000 1319.200000 1803.100000 1322.560000 ;
        RECT 1801.360000 1373.600000 1803.100000 1376.960000 ;
        RECT 1801.360000 1428.000000 1803.100000 1431.360000 ;
        RECT 1801.360000 1482.400000 1803.100000 1485.760000 ;
        RECT 1801.360000 1536.800000 1803.100000 1540.160000 ;
        RECT 1801.360000 1591.200000 1803.100000 1594.560000 ;
        RECT 1801.360000 1645.600000 1803.100000 1648.960000 ;
        RECT 1801.360000 1700.000000 1803.100000 1703.360000 ;
        RECT 1754.480000 1101.600000 1756.220000 1104.960000 ;
        RECT 1754.480000 1156.000000 1756.220000 1159.360000 ;
        RECT 1754.480000 1210.400000 1756.220000 1213.760000 ;
        RECT 1754.480000 1264.800000 1756.220000 1268.160000 ;
        RECT 1754.480000 1319.200000 1756.220000 1322.560000 ;
        RECT 1754.480000 1373.600000 1756.220000 1376.960000 ;
        RECT 1754.480000 1428.000000 1756.220000 1431.360000 ;
        RECT 1754.480000 1482.400000 1756.220000 1485.760000 ;
        RECT 1754.480000 1536.800000 1756.220000 1540.160000 ;
        RECT 1754.480000 1591.200000 1756.220000 1594.560000 ;
        RECT 1754.480000 1645.600000 1756.220000 1648.960000 ;
        RECT 1754.480000 1700.000000 1756.220000 1703.360000 ;
        RECT 1053.040000 557.600000 1054.780000 560.960000 ;
        RECT 1053.040000 612.000000 1054.780000 615.360000 ;
        RECT 1053.040000 666.400000 1054.780000 669.760000 ;
        RECT 1053.040000 720.800000 1054.780000 724.160000 ;
        RECT 1053.040000 775.200000 1054.780000 778.560000 ;
        RECT 1053.040000 829.600000 1054.780000 832.960000 ;
        RECT 1053.040000 884.000000 1054.780000 887.360000 ;
        RECT 1053.040000 938.400000 1054.780000 941.760000 ;
        RECT 576.360000 557.600000 578.100000 560.960000 ;
        RECT 576.360000 612.000000 578.100000 615.360000 ;
        RECT 576.360000 666.400000 578.100000 669.760000 ;
        RECT 576.360000 720.800000 578.100000 724.160000 ;
        RECT 576.360000 775.200000 578.100000 778.560000 ;
        RECT 576.360000 829.600000 578.100000 832.960000 ;
        RECT 576.360000 884.000000 578.100000 887.360000 ;
        RECT 576.360000 938.400000 578.100000 941.760000 ;
        RECT 528.040000 557.600000 529.780000 560.960000 ;
        RECT 528.040000 612.000000 529.780000 615.360000 ;
        RECT 528.040000 666.400000 529.780000 669.760000 ;
        RECT 528.040000 720.800000 529.780000 724.160000 ;
        RECT 528.040000 775.200000 529.780000 778.560000 ;
        RECT 528.040000 829.600000 529.780000 832.960000 ;
        RECT 528.040000 884.000000 529.780000 887.360000 ;
        RECT 528.040000 938.400000 529.780000 941.760000 ;
        RECT 51.360000 557.600000 53.100000 560.960000 ;
        RECT 51.360000 612.000000 53.100000 615.360000 ;
        RECT 51.360000 666.400000 53.100000 669.760000 ;
        RECT 51.360000 720.800000 53.100000 724.160000 ;
        RECT 51.360000 775.200000 53.100000 778.560000 ;
        RECT 51.360000 829.600000 53.100000 832.960000 ;
        RECT 51.360000 884.000000 53.100000 887.360000 ;
        RECT 51.360000 938.400000 53.100000 941.760000 ;
        RECT 576.360000 122.400000 578.100000 125.760000 ;
        RECT 576.360000 176.800000 578.100000 180.160000 ;
        RECT 576.360000 231.200000 578.100000 234.560000 ;
        RECT 576.360000 285.600000 578.100000 288.960000 ;
        RECT 576.360000 340.000000 578.100000 343.360000 ;
        RECT 576.360000 394.400000 578.100000 397.760000 ;
        RECT 576.360000 448.800000 578.100000 452.160000 ;
        RECT 528.040000 122.400000 529.780000 125.760000 ;
        RECT 528.040000 176.800000 529.780000 180.160000 ;
        RECT 528.040000 231.200000 529.780000 234.560000 ;
        RECT 528.040000 285.600000 529.780000 288.960000 ;
        RECT 528.040000 340.000000 529.780000 343.360000 ;
        RECT 528.040000 394.400000 529.780000 397.760000 ;
        RECT 528.040000 448.800000 529.780000 452.160000 ;
        RECT 51.360000 122.400000 53.100000 125.760000 ;
        RECT 51.360000 176.800000 53.100000 180.160000 ;
        RECT 51.360000 231.200000 53.100000 234.560000 ;
        RECT 51.360000 285.600000 53.100000 288.960000 ;
        RECT 51.360000 340.000000 53.100000 343.360000 ;
        RECT 51.360000 394.400000 53.100000 397.760000 ;
        RECT 51.360000 448.800000 53.100000 452.160000 ;
        RECT 1053.040000 122.400000 1054.780000 125.760000 ;
        RECT 1053.040000 176.800000 1054.780000 180.160000 ;
        RECT 1053.040000 231.200000 1054.780000 234.560000 ;
        RECT 1053.040000 285.600000 1054.780000 288.960000 ;
        RECT 1053.040000 340.000000 1054.780000 343.360000 ;
        RECT 1053.040000 394.400000 1054.780000 397.760000 ;
        RECT 1053.040000 448.800000 1054.780000 452.160000 ;
        RECT 2553.040000 557.600000 2554.780000 560.960000 ;
        RECT 2553.040000 612.000000 2554.780000 615.360000 ;
        RECT 2553.040000 666.400000 2554.780000 669.760000 ;
        RECT 2553.040000 720.800000 2554.780000 724.160000 ;
        RECT 2553.040000 775.200000 2554.780000 778.560000 ;
        RECT 2553.040000 829.600000 2554.780000 832.960000 ;
        RECT 2553.040000 884.000000 2554.780000 887.360000 ;
        RECT 2553.040000 938.400000 2554.780000 941.760000 ;
        RECT 2076.360000 557.600000 2078.100000 560.960000 ;
        RECT 2076.360000 612.000000 2078.100000 615.360000 ;
        RECT 2076.360000 666.400000 2078.100000 669.760000 ;
        RECT 2076.360000 720.800000 2078.100000 724.160000 ;
        RECT 2076.360000 775.200000 2078.100000 778.560000 ;
        RECT 2076.360000 829.600000 2078.100000 832.960000 ;
        RECT 2076.360000 884.000000 2078.100000 887.360000 ;
        RECT 2076.360000 938.400000 2078.100000 941.760000 ;
        RECT 2003.040000 557.600000 2004.780000 560.960000 ;
        RECT 2003.040000 612.000000 2004.780000 615.360000 ;
        RECT 2003.040000 666.400000 2004.780000 669.760000 ;
        RECT 2003.040000 720.800000 2004.780000 724.160000 ;
        RECT 2003.040000 775.200000 2004.780000 778.560000 ;
        RECT 2003.040000 829.600000 2004.780000 832.960000 ;
        RECT 2003.040000 884.000000 2004.780000 887.360000 ;
        RECT 2003.040000 938.400000 2004.780000 941.760000 ;
        RECT 1526.360000 557.600000 1528.100000 560.960000 ;
        RECT 1526.360000 612.000000 1528.100000 615.360000 ;
        RECT 1526.360000 666.400000 1528.100000 669.760000 ;
        RECT 1526.360000 720.800000 1528.100000 724.160000 ;
        RECT 1526.360000 775.200000 1528.100000 778.560000 ;
        RECT 1526.360000 829.600000 1528.100000 832.960000 ;
        RECT 1526.360000 884.000000 1528.100000 887.360000 ;
        RECT 1526.360000 938.400000 1528.100000 941.760000 ;
        RECT 1526.360000 122.400000 1528.100000 125.760000 ;
        RECT 1526.360000 176.800000 1528.100000 180.160000 ;
        RECT 1526.360000 231.200000 1528.100000 234.560000 ;
        RECT 1526.360000 285.600000 1528.100000 288.960000 ;
        RECT 1526.360000 340.000000 1528.100000 343.360000 ;
        RECT 1526.360000 394.400000 1528.100000 397.760000 ;
        RECT 1526.360000 448.800000 1528.100000 452.160000 ;
        RECT 2553.040000 122.400000 2554.780000 125.760000 ;
        RECT 2553.040000 176.800000 2554.780000 180.160000 ;
        RECT 2553.040000 231.200000 2554.780000 234.560000 ;
        RECT 2553.040000 285.600000 2554.780000 288.960000 ;
        RECT 2553.040000 340.000000 2554.780000 343.360000 ;
        RECT 2553.040000 394.400000 2554.780000 397.760000 ;
        RECT 2553.040000 448.800000 2554.780000 452.160000 ;
        RECT 2076.360000 122.400000 2078.100000 125.760000 ;
        RECT 2076.360000 176.800000 2078.100000 180.160000 ;
        RECT 2076.360000 231.200000 2078.100000 234.560000 ;
        RECT 2076.360000 285.600000 2078.100000 288.960000 ;
        RECT 2076.360000 340.000000 2078.100000 343.360000 ;
        RECT 2076.360000 394.400000 2078.100000 397.760000 ;
        RECT 2076.360000 448.800000 2078.100000 452.160000 ;
        RECT 2003.040000 122.400000 2004.780000 125.760000 ;
        RECT 2003.040000 176.800000 2004.780000 180.160000 ;
        RECT 2003.040000 231.200000 2004.780000 234.560000 ;
        RECT 2003.040000 285.600000 2004.780000 288.960000 ;
        RECT 2003.040000 340.000000 2004.780000 343.360000 ;
        RECT 2003.040000 394.400000 2004.780000 397.760000 ;
        RECT 2003.040000 448.800000 2004.780000 452.160000 ;
        RECT 724.480000 1754.400000 726.220000 1757.760000 ;
        RECT 724.480000 1808.800000 726.220000 1812.160000 ;
        RECT 724.480000 1863.200000 726.220000 1866.560000 ;
        RECT 724.480000 1917.600000 726.220000 1920.960000 ;
        RECT 724.480000 1972.000000 726.220000 1975.360000 ;
        RECT 724.480000 2026.400000 726.220000 2029.760000 ;
        RECT 724.480000 2080.800000 726.220000 2084.160000 ;
        RECT 724.480000 2135.200000 726.220000 2138.560000 ;
        RECT 724.480000 2189.600000 726.220000 2192.960000 ;
        RECT 724.480000 2244.000000 726.220000 2247.360000 ;
        RECT 724.480000 2298.400000 726.220000 2301.760000 ;
        RECT 724.480000 2352.800000 726.220000 2356.160000 ;
        RECT 724.480000 2407.200000 726.220000 2410.560000 ;
        RECT 38.360000 1863.200000 40.100000 1866.560000 ;
        RECT 38.360000 1917.600000 40.100000 1920.960000 ;
        RECT 38.360000 1972.000000 40.100000 1975.360000 ;
        RECT 38.360000 2026.400000 40.100000 2029.760000 ;
        RECT 38.360000 2080.800000 40.100000 2084.160000 ;
        RECT 38.360000 2135.200000 40.100000 2138.560000 ;
        RECT 38.360000 2189.600000 40.100000 2192.960000 ;
        RECT 38.360000 2244.000000 40.100000 2247.360000 ;
        RECT 38.360000 2298.400000 40.100000 2301.760000 ;
        RECT 38.360000 2352.800000 40.100000 2356.160000 ;
        RECT 38.360000 2407.200000 40.100000 2410.560000 ;
        RECT 27.200000 1808.800000 31.600000 1812.160000 ;
        RECT 27.200000 1863.200000 31.600000 1866.560000 ;
        RECT 27.200000 1917.600000 31.600000 1920.960000 ;
        RECT 27.200000 1972.000000 31.600000 1975.360000 ;
        RECT 27.200000 2026.400000 31.600000 2029.760000 ;
        RECT 27.200000 2080.800000 31.600000 2084.160000 ;
        RECT 27.200000 2135.200000 31.600000 2138.560000 ;
        RECT 27.200000 2189.600000 31.600000 2192.960000 ;
        RECT 27.200000 2244.000000 31.600000 2247.360000 ;
        RECT 27.200000 2298.400000 31.600000 2301.760000 ;
        RECT 27.200000 2352.800000 31.600000 2356.160000 ;
        RECT 27.200000 2407.200000 31.600000 2410.560000 ;
        RECT 732.980000 1808.800000 737.760000 1812.160000 ;
        RECT 732.980000 1863.200000 737.760000 1866.560000 ;
        RECT 732.980000 1917.600000 737.760000 1920.960000 ;
        RECT 732.980000 1972.000000 737.760000 1975.360000 ;
        RECT 732.980000 2026.400000 737.760000 2029.760000 ;
        RECT 732.980000 2080.800000 737.760000 2084.160000 ;
        RECT 732.980000 2135.200000 737.760000 2138.560000 ;
        RECT 732.980000 2189.600000 737.760000 2192.960000 ;
        RECT 732.980000 2244.000000 737.760000 2247.360000 ;
        RECT 732.980000 2298.400000 737.760000 2301.760000 ;
        RECT 732.980000 2352.800000 737.760000 2356.160000 ;
        RECT 732.980000 2407.200000 737.760000 2410.560000 ;
        RECT 771.360000 1808.800000 773.100000 1812.160000 ;
        RECT 771.360000 1863.200000 773.100000 1866.560000 ;
        RECT 771.360000 1917.600000 773.100000 1920.960000 ;
        RECT 771.360000 1972.000000 773.100000 1975.360000 ;
        RECT 771.360000 2026.400000 773.100000 2029.760000 ;
        RECT 771.360000 2080.800000 773.100000 2084.160000 ;
        RECT 771.360000 2135.200000 773.100000 2138.560000 ;
        RECT 771.360000 2189.600000 773.100000 2192.960000 ;
        RECT 771.360000 2244.000000 773.100000 2247.360000 ;
        RECT 771.360000 2298.400000 773.100000 2301.760000 ;
        RECT 771.360000 2352.800000 773.100000 2356.160000 ;
        RECT 771.360000 2407.200000 773.100000 2410.560000 ;
        RECT 771.360000 2461.600000 773.100000 2464.960000 ;
        RECT 1457.480000 1808.800000 1459.220000 1812.160000 ;
        RECT 1457.480000 1863.200000 1459.220000 1866.560000 ;
        RECT 1457.480000 1917.600000 1459.220000 1920.960000 ;
        RECT 1457.480000 1972.000000 1459.220000 1975.360000 ;
        RECT 1457.480000 2026.400000 1459.220000 2029.760000 ;
        RECT 1457.480000 2080.800000 1459.220000 2084.160000 ;
        RECT 1457.480000 2135.200000 1459.220000 2138.560000 ;
        RECT 1457.480000 2189.600000 1459.220000 2192.960000 ;
        RECT 1457.480000 2244.000000 1459.220000 2247.360000 ;
        RECT 1457.480000 2298.400000 1459.220000 2301.760000 ;
        RECT 1457.480000 2352.800000 1459.220000 2356.160000 ;
        RECT 1457.480000 2407.200000 1459.220000 2410.560000 ;
        RECT 1457.480000 2461.600000 1459.220000 2464.960000 ;
      LAYER met5 ;
        RECT 1059.800000 1042.800000 1764.780000 1044.600000 ;
        RECT 0.000000 4.080000 2605.900000 12.240000 ;
        RECT 4.500000 68.000000 2601.400000 71.360000 ;
        RECT 567.800000 82.800000 1063.340000 84.600000 ;
        RECT 567.800000 495.620000 1063.340000 497.420000 ;
        RECT 567.800000 542.800000 1063.340000 544.600000 ;
        RECT 42.800000 82.800000 538.340000 84.600000 ;
        RECT 42.800000 91.360000 52.430000 93.100000 ;
        RECT 42.800000 542.800000 538.340000 544.600000 ;
        RECT 42.800000 495.620000 538.340000 497.420000 ;
        RECT 528.710000 551.360000 538.340000 553.100000 ;
        RECT 1053.710000 91.360000 1064.160000 93.100000 ;
        RECT 1053.710000 551.360000 1064.160000 553.100000 ;
        RECT 4.500000 1047.200000 1061.800000 1050.560000 ;
        RECT 567.800000 955.620000 1063.340000 957.420000 ;
        RECT 42.800000 955.620000 538.340000 957.420000 ;
        RECT 1517.800000 82.800000 2013.340000 84.600000 ;
        RECT 1517.800000 495.620000 2013.340000 497.420000 ;
        RECT 1517.800000 542.800000 2013.340000 544.600000 ;
        RECT 2067.800000 82.800000 2563.340000 84.600000 ;
        RECT 2067.800000 495.620000 2563.340000 497.420000 ;
        RECT 2067.800000 542.800000 2563.340000 544.600000 ;
        RECT 2003.710000 487.120000 2013.340000 488.860000 ;
        RECT 2003.710000 551.360000 2013.340000 553.100000 ;
        RECT 2553.710000 487.120000 2563.340000 488.860000 ;
        RECT 2553.710000 551.360000 2563.340000 553.100000 ;
        RECT 1517.800000 955.620000 2013.340000 957.420000 ;
        RECT 1792.800000 1042.800000 2497.780000 1044.600000 ;
        RECT 1762.780000 1047.200000 1794.800000 1050.560000 ;
        RECT 1755.350000 1051.360000 1758.210000 1053.100000 ;
        RECT 2067.800000 955.620000 2563.340000 957.420000 ;
        RECT 2495.780000 1047.200000 2601.400000 1050.560000 ;
        RECT 2488.350000 1051.360000 2491.210000 1053.100000 ;
        RECT 1059.800000 1726.940000 1764.780000 1728.740000 ;
        RECT 762.800000 2476.940000 1467.780000 2478.740000 ;
        RECT 762.800000 1792.800000 1467.780000 1794.600000 ;
        RECT 0.000000 2590.800000 2605.900000 2598.960000 ;
        RECT 29.800000 1742.800000 734.780000 1744.600000 ;
        RECT 29.800000 1752.680000 39.230000 1754.420000 ;
        RECT 29.800000 2426.940000 734.780000 2428.740000 ;
        RECT 1792.800000 1726.940000 2497.780000 1728.740000 ;
        RECT 1458.150000 2468.440000 1467.780000 2470.180000 ;
        RECT 4.500000 1101.600000 2601.400000 1104.960000 ;
        RECT 4.500000 1156.000000 2601.400000 1159.360000 ;
        RECT 4.500000 1210.400000 2601.400000 1213.760000 ;
        RECT 4.500000 1264.800000 2601.400000 1268.160000 ;
        RECT 4.500000 1319.200000 2601.400000 1322.560000 ;
        RECT 4.500000 1373.600000 2601.400000 1376.960000 ;
        RECT 4.500000 1428.000000 2601.400000 1431.360000 ;
        RECT 4.500000 1482.400000 2601.400000 1485.760000 ;
        RECT 4.500000 1536.800000 2601.400000 1540.160000 ;
        RECT 4.500000 1591.200000 2601.400000 1594.560000 ;
        RECT 4.500000 1645.600000 2601.400000 1648.960000 ;
        RECT 4.500000 1700.000000 2601.400000 1703.360000 ;
        RECT 4.500000 1754.400000 2601.400000 1757.760000 ;
        RECT 4.500000 1808.800000 2601.400000 1812.160000 ;
        RECT 4.500000 1863.200000 2601.400000 1866.560000 ;
        RECT 4.500000 1917.600000 2601.400000 1920.960000 ;
        RECT 4.500000 1972.000000 2601.400000 1975.360000 ;
        RECT 4.500000 2026.400000 2601.400000 2029.760000 ;
        RECT 4.500000 2080.800000 2601.400000 2084.160000 ;
        RECT 4.500000 2135.200000 2601.400000 2138.560000 ;
        RECT 4.500000 2189.600000 2601.400000 2192.960000 ;
        RECT 4.500000 2244.000000 2601.400000 2247.360000 ;
        RECT 4.500000 2298.400000 2601.400000 2301.760000 ;
        RECT 4.500000 2352.800000 2601.400000 2356.160000 ;
        RECT 4.500000 2407.200000 2601.400000 2410.560000 ;
        RECT 4.500000 2461.600000 2601.400000 2464.960000 ;
        RECT 4.500000 2516.000000 2601.400000 2519.360000 ;
        RECT 4.500000 2570.400000 2601.400000 2573.760000 ;
        RECT 4.500000 122.400000 2601.400000 125.760000 ;
        RECT 4.500000 176.800000 2601.400000 180.160000 ;
        RECT 4.500000 231.200000 2601.400000 234.560000 ;
        RECT 4.500000 285.600000 2601.400000 288.960000 ;
        RECT 4.500000 340.000000 2601.400000 343.360000 ;
        RECT 4.500000 394.400000 2601.400000 397.760000 ;
        RECT 4.500000 448.800000 2601.400000 452.160000 ;
        RECT 4.500000 503.200000 2601.400000 506.560000 ;
        RECT 4.500000 557.600000 2601.400000 560.960000 ;
        RECT 4.500000 612.000000 2601.400000 615.360000 ;
        RECT 4.500000 666.400000 2601.400000 669.760000 ;
        RECT 4.500000 720.800000 2601.400000 724.160000 ;
        RECT 4.500000 775.200000 2601.400000 778.560000 ;
        RECT 4.500000 829.600000 2601.400000 832.960000 ;
        RECT 4.500000 884.000000 2601.400000 887.360000 ;
        RECT 4.500000 938.400000 2601.400000 941.760000 ;
        RECT 4.500000 992.800000 2601.400000 996.160000 ;
        RECT 51.360000 91.360000 53.100000 93.100000 ;
        RECT 528.040000 551.360000 529.780000 553.100000 ;
        RECT 1053.040000 91.360000 1054.780000 93.100000 ;
        RECT 1053.040000 551.360000 1054.780000 553.100000 ;
        RECT 2003.040000 487.120000 2004.780000 488.860000 ;
        RECT 2003.040000 551.360000 2004.780000 553.100000 ;
        RECT 2553.040000 487.120000 2554.780000 488.860000 ;
        RECT 2553.040000 551.360000 2554.780000 553.100000 ;
        RECT 1754.790000 1051.360000 1756.210000 1053.100000 ;
        RECT 1757.500000 1051.360000 1758.920000 1053.100000 ;
        RECT 2487.790000 1051.360000 2489.210000 1053.100000 ;
        RECT 2490.500000 1051.360000 2491.920000 1053.100000 ;
        RECT 29.800000 1752.435000 31.600000 1754.665000 ;
        RECT 38.360000 1752.400000 40.100000 1757.760000 ;
        RECT 1457.480000 2468.440000 1459.220000 2470.180000 ;
    END
# end of P/G power stripe data as pin

  END VSS
  PIN VDD
    DIRECTION INOUT ;
    USE POWER ;
    PORT
      LAYER met4 ;
        RECT 2581.000000 2594.880000 2589.160000 2603.040000 ;
    END
    PORT
      LAYER met4 ;
        RECT 2581.000000 0.000000 2589.160000 8.160000 ;
    END
    PORT
      LAYER met4 ;
        RECT 16.740000 2594.880000 24.900000 2603.040000 ;
    END
    PORT
      LAYER met4 ;
        RECT 16.740000 0.000000 24.900000 8.160000 ;
    END
    PORT
      LAYER met5 ;
        RECT 2597.740000 2578.560000 2605.900000 2586.720000 ;
    END
    PORT
      LAYER met5 ;
        RECT 0.000000 2578.560000 8.160000 2586.720000 ;
    END
    PORT
      LAYER met5 ;
        RECT 2597.740000 16.320000 2605.900000 24.480000 ;
    END
    PORT
      LAYER met5 ;
        RECT 0.000000 16.320000 8.160000 24.480000 ;
    END

# P/G power stripe data as pin
    PORT
      LAYER met4 ;
        RECT 639.200000 952.020000 642.560000 1748.200000 ;
        RECT 584.800000 952.020000 588.160000 1748.200000 ;
        RECT 530.400000 952.020000 533.760000 1748.200000 ;
        RECT 476.000000 952.020000 479.360000 1748.200000 ;
        RECT 40.800000 957.820000 44.160000 1748.200000 ;
        RECT 16.740000 0.000000 24.900000 2603.040000 ;
        RECT 95.200000 952.020000 98.560000 1748.200000 ;
        RECT 149.600000 952.020000 152.960000 1748.200000 ;
        RECT 204.000000 952.020000 207.360000 1748.200000 ;
        RECT 258.400000 952.020000 261.760000 1748.200000 ;
        RECT 312.800000 952.020000 316.160000 1748.200000 ;
        RECT 367.200000 952.020000 370.560000 1748.200000 ;
        RECT 421.600000 952.020000 424.960000 1748.200000 ;
        RECT 1063.400000 1046.400000 1065.200000 1725.140000 ;
        RECT 748.000000 952.020000 751.360000 2586.720000 ;
        RECT 1020.000000 952.020000 1023.360000 1798.200000 ;
        RECT 965.600000 952.020000 968.960000 1798.200000 ;
        RECT 911.200000 952.020000 914.560000 1798.200000 ;
        RECT 856.800000 952.020000 860.160000 1798.200000 ;
        RECT 802.400000 952.020000 805.760000 1798.200000 ;
        RECT 693.600000 952.020000 696.960000 1748.200000 ;
        RECT 2492.380000 1046.400000 2494.180000 1725.140000 ;
        RECT 1796.400000 1046.400000 1798.200000 1725.140000 ;
        RECT 1759.380000 1046.400000 1761.180000 1725.140000 ;
        RECT 2543.200000 952.020000 2546.560000 2586.720000 ;
        RECT 1781.600000 952.020000 1784.960000 2586.720000 ;
        RECT 2581.000000 0.000000 2589.160000 2603.040000 ;
        RECT 1057.940000 546.400000 1059.740000 953.820000 ;
        RECT 571.400000 546.400000 573.200000 953.820000 ;
        RECT 532.940000 546.400000 534.740000 953.820000 ;
        RECT 46.400000 546.400000 48.200000 953.820000 ;
        RECT 1292.000000 16.320000 1295.360000 1048.200000 ;
        RECT 1237.600000 16.320000 1240.960000 1048.200000 ;
        RECT 1183.200000 16.320000 1186.560000 1048.200000 ;
        RECT 1128.800000 16.320000 1132.160000 1048.200000 ;
        RECT 1074.400000 16.320000 1077.760000 1048.200000 ;
        RECT 571.400000 86.400000 573.200000 493.820000 ;
        RECT 532.940000 86.400000 534.740000 493.820000 ;
        RECT 46.400000 86.400000 48.200000 493.820000 ;
        RECT 95.200000 16.320000 98.560000 88.200000 ;
        RECT 40.800000 16.320000 44.160000 82.400000 ;
        RECT 40.800000 497.820000 44.160000 542.400000 ;
        RECT 95.200000 492.020000 98.560000 548.200000 ;
        RECT 1057.940000 86.400000 1059.740000 493.820000 ;
        RECT 2557.940000 546.400000 2559.740000 953.820000 ;
        RECT 2071.400000 546.400000 2073.200000 953.820000 ;
        RECT 2007.940000 546.400000 2009.740000 953.820000 ;
        RECT 1521.400000 546.400000 1523.200000 953.820000 ;
        RECT 2053.600000 16.320000 2056.960000 1048.200000 ;
        RECT 1509.600000 16.320000 1512.960000 1048.200000 ;
        RECT 1455.200000 16.320000 1458.560000 1048.200000 ;
        RECT 1400.800000 16.320000 1404.160000 1048.200000 ;
        RECT 1346.400000 16.320000 1349.760000 1048.200000 ;
        RECT 1521.400000 86.400000 1523.200000 493.820000 ;
        RECT 1564.000000 16.320000 1567.360000 88.200000 ;
        RECT 1564.000000 492.020000 1567.360000 548.200000 ;
        RECT 2557.940000 86.400000 2559.740000 493.820000 ;
        RECT 2071.400000 86.400000 2073.200000 493.820000 ;
        RECT 2007.940000 86.400000 2009.740000 493.820000 ;
        RECT 1944.800000 952.020000 1948.160000 1048.200000 ;
        RECT 1890.400000 952.020000 1893.760000 1048.200000 ;
        RECT 1836.000000 952.020000 1839.360000 1048.200000 ;
        RECT 1727.200000 952.020000 1730.560000 1048.200000 ;
        RECT 1672.800000 952.020000 1676.160000 1048.200000 ;
        RECT 1618.400000 952.020000 1621.760000 1048.200000 ;
        RECT 1564.000000 952.020000 1567.360000 1048.200000 ;
        RECT 2434.400000 952.020000 2437.760000 1048.200000 ;
        RECT 2380.000000 952.020000 2383.360000 1048.200000 ;
        RECT 2325.600000 952.020000 2328.960000 1048.200000 ;
        RECT 2271.200000 952.020000 2274.560000 1048.200000 ;
        RECT 2216.800000 952.020000 2220.160000 1048.200000 ;
        RECT 2162.400000 952.020000 2165.760000 1048.200000 ;
        RECT 2108.000000 952.020000 2111.360000 1048.200000 ;
        RECT 1999.200000 952.020000 2002.560000 1048.200000 ;
        RECT 2488.800000 952.020000 2492.160000 1041.120000 ;
        RECT 766.400000 1796.400000 768.200000 2475.140000 ;
        RECT 729.380000 1746.400000 731.180000 2425.140000 ;
        RECT 33.400000 1746.400000 35.200000 2425.140000 ;
        RECT 1074.400000 1723.340000 1077.760000 1798.200000 ;
        RECT 1128.800000 1723.340000 1132.160000 1798.200000 ;
        RECT 1183.200000 1723.340000 1186.560000 1798.200000 ;
        RECT 1237.600000 1723.340000 1240.960000 1798.200000 ;
        RECT 1292.000000 1723.340000 1295.360000 1798.200000 ;
        RECT 312.800000 2423.340000 316.160000 2586.720000 ;
        RECT 258.400000 2423.340000 261.760000 2586.720000 ;
        RECT 204.000000 2423.340000 207.360000 2586.720000 ;
        RECT 149.600000 2423.340000 152.960000 2586.720000 ;
        RECT 95.200000 2423.340000 98.560000 2586.720000 ;
        RECT 40.800000 2423.340000 44.160000 2586.720000 ;
        RECT 639.200000 2423.340000 642.560000 2586.720000 ;
        RECT 584.800000 2423.340000 588.160000 2586.720000 ;
        RECT 530.400000 2423.340000 533.760000 2586.720000 ;
        RECT 476.000000 2423.340000 479.360000 2586.720000 ;
        RECT 421.600000 2423.340000 424.960000 2586.720000 ;
        RECT 367.200000 2423.340000 370.560000 2586.720000 ;
        RECT 693.600000 2423.340000 696.960000 2586.720000 ;
        RECT 1292.000000 2473.340000 1295.360000 2586.720000 ;
        RECT 1237.600000 2473.340000 1240.960000 2586.720000 ;
        RECT 1183.200000 2473.340000 1186.560000 2586.720000 ;
        RECT 1128.800000 2473.340000 1132.160000 2586.720000 ;
        RECT 1074.400000 2473.340000 1077.760000 2586.720000 ;
        RECT 1020.000000 2473.340000 1023.360000 2586.720000 ;
        RECT 965.600000 2473.340000 968.960000 2586.720000 ;
        RECT 911.200000 2473.340000 914.560000 2586.720000 ;
        RECT 856.800000 2473.340000 860.160000 2586.720000 ;
        RECT 802.400000 2473.340000 805.760000 2586.720000 ;
        RECT 1462.380000 1796.400000 1464.180000 2475.140000 ;
        RECT 1509.600000 1723.340000 1512.960000 2586.720000 ;
        RECT 1564.000000 1723.340000 1567.360000 2586.720000 ;
        RECT 1618.400000 1723.340000 1621.760000 2586.720000 ;
        RECT 1672.800000 1723.340000 1676.160000 2586.720000 ;
        RECT 1727.200000 1723.340000 1730.560000 2586.720000 ;
        RECT 1836.000000 1723.340000 1839.360000 2586.720000 ;
        RECT 1890.400000 1723.340000 1893.760000 2586.720000 ;
        RECT 1944.800000 1723.340000 1948.160000 2586.720000 ;
        RECT 2434.400000 1723.340000 2437.760000 2586.720000 ;
        RECT 2380.000000 1723.340000 2383.360000 2586.720000 ;
        RECT 2325.600000 1723.340000 2328.960000 2586.720000 ;
        RECT 2271.200000 1723.340000 2274.560000 2586.720000 ;
        RECT 2216.800000 1723.340000 2220.160000 2586.720000 ;
        RECT 2162.400000 1723.340000 2165.760000 2586.720000 ;
        RECT 2108.000000 1723.340000 2111.360000 2586.720000 ;
        RECT 2488.800000 1729.140000 2492.160000 2586.720000 ;
        RECT 1999.200000 1723.340000 2002.560000 2586.720000 ;
        RECT 2053.600000 1723.340000 2056.960000 2586.720000 ;
        RECT 1455.200000 1723.340000 1458.560000 1798.200000 ;
        RECT 1400.800000 1723.340000 1404.160000 1798.200000 ;
        RECT 1346.400000 1723.340000 1349.760000 1798.200000 ;
        RECT 1455.200000 2473.340000 1458.560000 2586.720000 ;
        RECT 1400.800000 2473.340000 1404.160000 2586.720000 ;
        RECT 1346.400000 2473.340000 1349.760000 2586.720000 ;
        RECT 149.600000 492.020000 152.960000 548.200000 ;
        RECT 204.000000 492.020000 207.360000 548.200000 ;
        RECT 258.400000 492.020000 261.760000 548.200000 ;
        RECT 312.800000 492.020000 316.160000 548.200000 ;
        RECT 367.200000 492.020000 370.560000 548.200000 ;
        RECT 421.600000 492.020000 424.960000 548.200000 ;
        RECT 476.000000 492.020000 479.360000 548.200000 ;
        RECT 530.400000 492.020000 533.760000 548.200000 ;
        RECT 584.800000 492.020000 588.160000 548.200000 ;
        RECT 639.200000 492.020000 642.560000 548.200000 ;
        RECT 693.600000 492.020000 696.960000 548.200000 ;
        RECT 748.000000 492.020000 751.360000 548.200000 ;
        RECT 802.400000 492.020000 805.760000 548.200000 ;
        RECT 856.800000 492.020000 860.160000 548.200000 ;
        RECT 911.200000 492.020000 914.560000 548.200000 ;
        RECT 965.600000 492.020000 968.960000 548.200000 ;
        RECT 1020.000000 492.020000 1023.360000 548.200000 ;
        RECT 149.600000 16.320000 152.960000 88.200000 ;
        RECT 204.000000 16.320000 207.360000 88.200000 ;
        RECT 258.400000 16.320000 261.760000 88.200000 ;
        RECT 312.800000 16.320000 316.160000 88.200000 ;
        RECT 367.200000 16.320000 370.560000 88.200000 ;
        RECT 421.600000 16.320000 424.960000 88.200000 ;
        RECT 476.000000 16.320000 479.360000 88.200000 ;
        RECT 530.400000 16.320000 533.760000 88.200000 ;
        RECT 584.800000 16.320000 588.160000 88.200000 ;
        RECT 639.200000 16.320000 642.560000 88.200000 ;
        RECT 693.600000 16.320000 696.960000 88.200000 ;
        RECT 748.000000 16.320000 751.360000 88.200000 ;
        RECT 802.400000 16.320000 805.760000 88.200000 ;
        RECT 856.800000 16.320000 860.160000 88.200000 ;
        RECT 911.200000 16.320000 914.560000 88.200000 ;
        RECT 965.600000 16.320000 968.960000 88.200000 ;
        RECT 1020.000000 16.320000 1023.360000 88.200000 ;
        RECT 1618.400000 492.020000 1621.760000 548.200000 ;
        RECT 1672.800000 492.020000 1676.160000 548.200000 ;
        RECT 1727.200000 492.020000 1730.560000 548.200000 ;
        RECT 1781.600000 492.020000 1784.960000 548.200000 ;
        RECT 1836.000000 492.020000 1839.360000 548.200000 ;
        RECT 1890.400000 492.020000 1893.760000 548.200000 ;
        RECT 1944.800000 492.020000 1948.160000 548.200000 ;
        RECT 1999.200000 492.020000 2002.560000 548.200000 ;
        RECT 1618.400000 16.320000 1621.760000 88.200000 ;
        RECT 1672.800000 16.320000 1676.160000 88.200000 ;
        RECT 1727.200000 16.320000 1730.560000 88.200000 ;
        RECT 1781.600000 16.320000 1784.960000 88.200000 ;
        RECT 1836.000000 16.320000 1839.360000 88.200000 ;
        RECT 1890.400000 16.320000 1893.760000 88.200000 ;
        RECT 1944.800000 16.320000 1948.160000 88.200000 ;
        RECT 1999.200000 16.320000 2002.560000 88.200000 ;
        RECT 2108.000000 16.320000 2111.360000 88.200000 ;
        RECT 2162.400000 16.320000 2165.760000 88.200000 ;
        RECT 2216.800000 16.320000 2220.160000 88.200000 ;
        RECT 2271.200000 16.320000 2274.560000 88.200000 ;
        RECT 2325.600000 16.320000 2328.960000 88.200000 ;
        RECT 2380.000000 16.320000 2383.360000 88.200000 ;
        RECT 2434.400000 16.320000 2437.760000 88.200000 ;
        RECT 2488.800000 16.320000 2492.160000 88.200000 ;
        RECT 2543.200000 16.320000 2546.560000 88.200000 ;
        RECT 2108.000000 492.020000 2111.360000 548.200000 ;
        RECT 2162.400000 492.020000 2165.760000 548.200000 ;
        RECT 2216.800000 492.020000 2220.160000 548.200000 ;
        RECT 2271.200000 492.020000 2274.560000 548.200000 ;
        RECT 2325.600000 492.020000 2328.960000 548.200000 ;
        RECT 2380.000000 492.020000 2383.360000 548.200000 ;
        RECT 2434.400000 492.020000 2437.760000 548.200000 ;
        RECT 2488.800000 492.020000 2492.160000 548.200000 ;
        RECT 2543.200000 492.020000 2546.560000 548.200000 ;
        RECT 39.780000 81.600000 41.200000 83.020000 ;
        RECT 530.400000 86.400000 534.740000 88.200000 ;
        RECT 54.760000 483.720000 56.500000 485.460000 ;
        RECT 530.400000 546.400000 534.740000 548.200000 ;
        RECT 530.400000 492.020000 534.740000 493.820000 ;
        RECT 1049.640000 94.760000 1051.380000 96.500000 ;
        RECT 530.400000 952.020000 534.740000 953.820000 ;
        RECT 54.760000 943.720000 56.500000 945.460000 ;
        RECT 1049.640000 943.720000 1051.380000 945.460000 ;
        RECT 2079.760000 94.760000 2081.500000 96.500000 ;
        RECT 1999.640000 483.720000 2001.380000 485.460000 ;
        RECT 2079.760000 943.720000 2081.500000 945.460000 ;
        RECT 1999.640000 943.720000 2001.380000 945.460000 ;
        RECT 41.760000 1768.000000 43.500000 1771.360000 ;
        RECT 1071.760000 1713.600000 1073.500000 1716.780000 ;
        RECT 41.760000 2415.040000 43.500000 2416.780000 ;
        RECT 1454.080000 1804.760000 1455.820000 1806.500000 ;
        RECT 2484.080000 1713.600000 2485.820000 1716.780000 ;
        RECT 1804.760000 1713.600000 1806.500000 1716.780000 ;
        RECT 1751.080000 1713.600000 1752.820000 1716.780000 ;
        RECT 1071.760000 1060.800000 1073.500000 1064.160000 ;
        RECT 1071.760000 1115.200000 1073.500000 1118.560000 ;
        RECT 1071.760000 1169.600000 1073.500000 1172.960000 ;
        RECT 1071.760000 1224.000000 1073.500000 1227.360000 ;
        RECT 1071.760000 1278.400000 1073.500000 1281.760000 ;
        RECT 1071.760000 1332.800000 1073.500000 1336.160000 ;
        RECT 1071.760000 1387.200000 1073.500000 1390.560000 ;
        RECT 1071.760000 1441.600000 1073.500000 1444.960000 ;
        RECT 1071.760000 1496.000000 1073.500000 1499.360000 ;
        RECT 1071.760000 1550.400000 1073.500000 1553.760000 ;
        RECT 1071.760000 1604.800000 1073.500000 1608.160000 ;
        RECT 1071.760000 1659.200000 1073.500000 1662.560000 ;
        RECT 2484.080000 1060.800000 2485.820000 1064.160000 ;
        RECT 2484.080000 1115.200000 2485.820000 1118.560000 ;
        RECT 2484.080000 1169.600000 2485.820000 1172.960000 ;
        RECT 2484.080000 1224.000000 2485.820000 1227.360000 ;
        RECT 2484.080000 1278.400000 2485.820000 1281.760000 ;
        RECT 2484.080000 1332.800000 2485.820000 1336.160000 ;
        RECT 2484.080000 1387.200000 2485.820000 1390.560000 ;
        RECT 2484.080000 1441.600000 2485.820000 1444.960000 ;
        RECT 2484.080000 1496.000000 2485.820000 1499.360000 ;
        RECT 2484.080000 1550.400000 2485.820000 1553.760000 ;
        RECT 2484.080000 1604.800000 2485.820000 1608.160000 ;
        RECT 2484.080000 1659.200000 2485.820000 1662.560000 ;
        RECT 1804.760000 1060.800000 1806.500000 1064.160000 ;
        RECT 1804.760000 1115.200000 1806.500000 1118.560000 ;
        RECT 1804.760000 1169.600000 1806.500000 1172.960000 ;
        RECT 1804.760000 1224.000000 1806.500000 1227.360000 ;
        RECT 1804.760000 1278.400000 1806.500000 1281.760000 ;
        RECT 1804.760000 1332.800000 1806.500000 1336.160000 ;
        RECT 1804.760000 1387.200000 1806.500000 1390.560000 ;
        RECT 1804.760000 1441.600000 1806.500000 1444.960000 ;
        RECT 1804.760000 1496.000000 1806.500000 1499.360000 ;
        RECT 1804.760000 1550.400000 1806.500000 1553.760000 ;
        RECT 1804.760000 1604.800000 1806.500000 1608.160000 ;
        RECT 1804.760000 1659.200000 1806.500000 1662.560000 ;
        RECT 1751.080000 1060.800000 1752.820000 1064.160000 ;
        RECT 1751.080000 1115.200000 1752.820000 1118.560000 ;
        RECT 1751.080000 1169.600000 1752.820000 1172.960000 ;
        RECT 1751.080000 1224.000000 1752.820000 1227.360000 ;
        RECT 1751.080000 1278.400000 1752.820000 1281.760000 ;
        RECT 1751.080000 1332.800000 1752.820000 1336.160000 ;
        RECT 1751.080000 1387.200000 1752.820000 1390.560000 ;
        RECT 1751.080000 1441.600000 1752.820000 1444.960000 ;
        RECT 1751.080000 1496.000000 1752.820000 1499.360000 ;
        RECT 1751.080000 1550.400000 1752.820000 1553.760000 ;
        RECT 1751.080000 1604.800000 1752.820000 1608.160000 ;
        RECT 1751.080000 1659.200000 1752.820000 1662.560000 ;
        RECT 1049.640000 571.200000 1051.380000 574.560000 ;
        RECT 1049.640000 625.600000 1051.380000 628.960000 ;
        RECT 1049.640000 680.000000 1051.380000 683.360000 ;
        RECT 1049.640000 734.400000 1051.380000 737.760000 ;
        RECT 1049.640000 788.800000 1051.380000 792.160000 ;
        RECT 1049.640000 843.200000 1051.380000 846.560000 ;
        RECT 1049.640000 897.600000 1051.380000 900.960000 ;
        RECT 579.760000 571.200000 581.500000 574.560000 ;
        RECT 579.760000 625.600000 581.500000 628.960000 ;
        RECT 579.760000 680.000000 581.500000 683.360000 ;
        RECT 579.760000 734.400000 581.500000 737.760000 ;
        RECT 579.760000 788.800000 581.500000 792.160000 ;
        RECT 579.760000 843.200000 581.500000 846.560000 ;
        RECT 579.760000 897.600000 581.500000 900.960000 ;
        RECT 524.640000 571.200000 526.380000 574.560000 ;
        RECT 524.640000 625.600000 526.380000 628.960000 ;
        RECT 524.640000 680.000000 526.380000 683.360000 ;
        RECT 524.640000 734.400000 526.380000 737.760000 ;
        RECT 524.640000 788.800000 526.380000 792.160000 ;
        RECT 524.640000 843.200000 526.380000 846.560000 ;
        RECT 524.640000 897.600000 526.380000 900.960000 ;
        RECT 54.760000 571.200000 56.500000 574.560000 ;
        RECT 54.760000 625.600000 56.500000 628.960000 ;
        RECT 54.760000 680.000000 56.500000 683.360000 ;
        RECT 54.760000 734.400000 56.500000 737.760000 ;
        RECT 54.760000 788.800000 56.500000 792.160000 ;
        RECT 54.760000 843.200000 56.500000 846.560000 ;
        RECT 54.760000 897.600000 56.500000 900.960000 ;
        RECT 579.760000 136.000000 581.500000 139.360000 ;
        RECT 579.760000 190.400000 581.500000 193.760000 ;
        RECT 579.760000 244.800000 581.500000 248.160000 ;
        RECT 579.760000 299.200000 581.500000 302.560000 ;
        RECT 579.760000 353.600000 581.500000 356.960000 ;
        RECT 579.760000 408.000000 581.500000 411.360000 ;
        RECT 579.760000 462.400000 581.500000 465.760000 ;
        RECT 524.640000 136.000000 526.380000 139.360000 ;
        RECT 524.640000 190.400000 526.380000 193.760000 ;
        RECT 524.640000 244.800000 526.380000 248.160000 ;
        RECT 524.640000 299.200000 526.380000 302.560000 ;
        RECT 524.640000 353.600000 526.380000 356.960000 ;
        RECT 524.640000 408.000000 526.380000 411.360000 ;
        RECT 524.640000 462.400000 526.380000 465.760000 ;
        RECT 54.760000 136.000000 56.500000 139.360000 ;
        RECT 54.760000 190.400000 56.500000 193.760000 ;
        RECT 54.760000 244.800000 56.500000 248.160000 ;
        RECT 54.760000 299.200000 56.500000 302.560000 ;
        RECT 54.760000 353.600000 56.500000 356.960000 ;
        RECT 54.760000 408.000000 56.500000 411.360000 ;
        RECT 54.760000 462.400000 56.500000 465.760000 ;
        RECT 1049.640000 136.000000 1051.380000 139.360000 ;
        RECT 1049.640000 190.400000 1051.380000 193.760000 ;
        RECT 1049.640000 244.800000 1051.380000 248.160000 ;
        RECT 1049.640000 299.200000 1051.380000 302.560000 ;
        RECT 1049.640000 353.600000 1051.380000 356.960000 ;
        RECT 1049.640000 408.000000 1051.380000 411.360000 ;
        RECT 1049.640000 462.400000 1051.380000 465.760000 ;
        RECT 2549.640000 571.200000 2551.380000 574.560000 ;
        RECT 2549.640000 625.600000 2551.380000 628.960000 ;
        RECT 2549.640000 680.000000 2551.380000 683.360000 ;
        RECT 2549.640000 734.400000 2551.380000 737.760000 ;
        RECT 2549.640000 788.800000 2551.380000 792.160000 ;
        RECT 2549.640000 843.200000 2551.380000 846.560000 ;
        RECT 2549.640000 897.600000 2551.380000 900.960000 ;
        RECT 2079.760000 571.200000 2081.500000 574.560000 ;
        RECT 2079.760000 625.600000 2081.500000 628.960000 ;
        RECT 2079.760000 680.000000 2081.500000 683.360000 ;
        RECT 2079.760000 734.400000 2081.500000 737.760000 ;
        RECT 2079.760000 788.800000 2081.500000 792.160000 ;
        RECT 2079.760000 843.200000 2081.500000 846.560000 ;
        RECT 2079.760000 897.600000 2081.500000 900.960000 ;
        RECT 1999.640000 571.200000 2001.380000 574.560000 ;
        RECT 1999.640000 625.600000 2001.380000 628.960000 ;
        RECT 1999.640000 680.000000 2001.380000 683.360000 ;
        RECT 1999.640000 734.400000 2001.380000 737.760000 ;
        RECT 1999.640000 788.800000 2001.380000 792.160000 ;
        RECT 1999.640000 843.200000 2001.380000 846.560000 ;
        RECT 1999.640000 897.600000 2001.380000 900.960000 ;
        RECT 1529.760000 571.200000 1531.500000 574.560000 ;
        RECT 1529.760000 625.600000 1531.500000 628.960000 ;
        RECT 1529.760000 680.000000 1531.500000 683.360000 ;
        RECT 1529.760000 734.400000 1531.500000 737.760000 ;
        RECT 1529.760000 788.800000 1531.500000 792.160000 ;
        RECT 1529.760000 843.200000 1531.500000 846.560000 ;
        RECT 1529.760000 897.600000 1531.500000 900.960000 ;
        RECT 1529.760000 136.000000 1531.500000 139.360000 ;
        RECT 1529.760000 190.400000 1531.500000 193.760000 ;
        RECT 1529.760000 244.800000 1531.500000 248.160000 ;
        RECT 1529.760000 299.200000 1531.500000 302.560000 ;
        RECT 1529.760000 353.600000 1531.500000 356.960000 ;
        RECT 1529.760000 408.000000 1531.500000 411.360000 ;
        RECT 1529.760000 462.400000 1531.500000 465.760000 ;
        RECT 2549.640000 136.000000 2551.380000 139.360000 ;
        RECT 2549.640000 190.400000 2551.380000 193.760000 ;
        RECT 2549.640000 244.800000 2551.380000 248.160000 ;
        RECT 2549.640000 299.200000 2551.380000 302.560000 ;
        RECT 2549.640000 353.600000 2551.380000 356.960000 ;
        RECT 2549.640000 408.000000 2551.380000 411.360000 ;
        RECT 2549.640000 462.400000 2551.380000 465.760000 ;
        RECT 2079.760000 136.000000 2081.500000 139.360000 ;
        RECT 2079.760000 190.400000 2081.500000 193.760000 ;
        RECT 2079.760000 244.800000 2081.500000 248.160000 ;
        RECT 2079.760000 299.200000 2081.500000 302.560000 ;
        RECT 2079.760000 353.600000 2081.500000 356.960000 ;
        RECT 2079.760000 408.000000 2081.500000 411.360000 ;
        RECT 2079.760000 462.400000 2081.500000 465.760000 ;
        RECT 1999.640000 136.000000 2001.380000 139.360000 ;
        RECT 1999.640000 190.400000 2001.380000 193.760000 ;
        RECT 1999.640000 244.800000 2001.380000 248.160000 ;
        RECT 1999.640000 299.200000 2001.380000 302.560000 ;
        RECT 1999.640000 353.600000 2001.380000 356.960000 ;
        RECT 1999.640000 408.000000 2001.380000 411.360000 ;
        RECT 1999.640000 462.400000 2001.380000 465.760000 ;
        RECT 721.080000 1768.000000 722.820000 1771.360000 ;
        RECT 721.080000 1822.400000 722.820000 1825.760000 ;
        RECT 721.080000 1876.800000 722.820000 1880.160000 ;
        RECT 721.080000 1931.200000 722.820000 1934.560000 ;
        RECT 721.080000 1985.600000 722.820000 1988.960000 ;
        RECT 721.080000 2040.000000 722.820000 2043.360000 ;
        RECT 721.080000 2094.400000 722.820000 2097.760000 ;
        RECT 721.080000 2148.800000 722.820000 2152.160000 ;
        RECT 721.080000 2203.200000 722.820000 2206.560000 ;
        RECT 721.080000 2257.600000 722.820000 2260.960000 ;
        RECT 721.080000 2312.000000 722.820000 2315.360000 ;
        RECT 721.080000 2366.400000 722.820000 2369.760000 ;
        RECT 41.760000 1822.400000 43.500000 1825.760000 ;
        RECT 41.760000 1876.800000 43.500000 1880.160000 ;
        RECT 41.760000 1931.200000 43.500000 1934.560000 ;
        RECT 41.760000 1985.600000 43.500000 1988.960000 ;
        RECT 41.760000 2040.000000 43.500000 2043.360000 ;
        RECT 41.760000 2094.400000 43.500000 2097.760000 ;
        RECT 41.760000 2148.800000 43.500000 2152.160000 ;
        RECT 41.760000 2203.200000 43.500000 2206.560000 ;
        RECT 41.760000 2257.600000 43.500000 2260.960000 ;
        RECT 41.760000 2312.000000 43.500000 2315.360000 ;
        RECT 41.760000 2366.400000 43.500000 2369.760000 ;
        RECT 774.760000 1822.400000 776.500000 1825.760000 ;
        RECT 774.760000 1876.800000 776.500000 1880.160000 ;
        RECT 774.760000 1931.200000 776.500000 1934.560000 ;
        RECT 774.760000 1985.600000 776.500000 1988.960000 ;
        RECT 774.760000 2040.000000 776.500000 2043.360000 ;
        RECT 774.760000 2094.400000 776.500000 2097.760000 ;
        RECT 774.760000 2148.800000 776.500000 2152.160000 ;
        RECT 774.760000 2203.200000 776.500000 2206.560000 ;
        RECT 774.760000 2257.600000 776.500000 2260.960000 ;
        RECT 774.760000 2312.000000 776.500000 2315.360000 ;
        RECT 774.760000 2366.400000 776.500000 2369.760000 ;
        RECT 774.760000 2420.800000 776.500000 2424.160000 ;
        RECT 1454.080000 1822.400000 1455.820000 1825.760000 ;
        RECT 1454.080000 1876.800000 1455.820000 1880.160000 ;
        RECT 1454.080000 1931.200000 1455.820000 1934.560000 ;
        RECT 1454.080000 1985.600000 1455.820000 1988.960000 ;
        RECT 1454.080000 2040.000000 1455.820000 2043.360000 ;
        RECT 1454.080000 2094.400000 1455.820000 2097.760000 ;
        RECT 1454.080000 2148.800000 1455.820000 2152.160000 ;
        RECT 1454.080000 2203.200000 1455.820000 2206.560000 ;
        RECT 1454.080000 2257.600000 1455.820000 2260.960000 ;
        RECT 1454.080000 2312.000000 1455.820000 2315.360000 ;
        RECT 1454.080000 2366.400000 1455.820000 2369.760000 ;
        RECT 1454.080000 2420.800000 1455.820000 2424.160000 ;
      LAYER met5 ;
        RECT 1063.400000 1046.400000 1761.180000 1048.200000 ;
        RECT 16.740000 136.000000 2589.160000 139.360000 ;
        RECT 16.740000 27.200000 2589.160000 30.560000 ;
        RECT 1064.940000 952.000000 1516.200000 955.360000 ;
        RECT 1064.940000 81.600000 1516.200000 84.960000 ;
        RECT 0.000000 16.320000 2605.900000 24.480000 ;
        RECT 571.400000 546.400000 1059.740000 548.200000 ;
        RECT 571.400000 492.020000 1059.740000 493.820000 ;
        RECT 571.400000 86.400000 1059.740000 88.200000 ;
        RECT 46.400000 86.400000 534.740000 88.200000 ;
        RECT 16.740000 81.600000 41.200000 84.960000 ;
        RECT 539.940000 81.600000 566.200000 84.960000 ;
        RECT 46.400000 546.400000 534.740000 548.200000 ;
        RECT 46.400000 492.020000 534.740000 493.820000 ;
        RECT 46.400000 483.720000 55.830000 485.460000 ;
        RECT 1050.310000 94.760000 1059.740000 96.500000 ;
        RECT 571.400000 952.020000 1059.740000 953.820000 ;
        RECT 16.740000 952.000000 41.200000 955.360000 ;
        RECT 539.940000 952.000000 566.200000 955.360000 ;
        RECT 46.400000 943.720000 55.830000 945.460000 ;
        RECT 46.400000 952.020000 534.740000 953.820000 ;
        RECT 1050.310000 943.720000 1059.740000 945.460000 ;
        RECT 1521.400000 546.400000 2009.740000 548.200000 ;
        RECT 1521.400000 492.020000 2009.740000 493.820000 ;
        RECT 1521.400000 86.400000 2009.740000 88.200000 ;
        RECT 2071.400000 86.400000 2559.740000 88.200000 ;
        RECT 2071.400000 94.760000 2080.830000 96.500000 ;
        RECT 2014.940000 81.600000 2066.200000 84.960000 ;
        RECT 2564.940000 81.600000 2589.160000 84.960000 ;
        RECT 2071.400000 546.400000 2559.740000 548.200000 ;
        RECT 2071.400000 492.020000 2559.740000 493.820000 ;
        RECT 1999.640000 484.590000 2001.380000 493.150000 ;
        RECT 1796.400000 1046.400000 2494.180000 1048.200000 ;
        RECT 1521.400000 952.020000 2009.740000 953.820000 ;
        RECT 1999.640000 944.590000 2001.380000 953.150000 ;
        RECT 2564.940000 952.000000 2589.160000 955.360000 ;
        RECT 2014.940000 952.000000 2066.200000 955.360000 ;
        RECT 2071.400000 943.720000 2080.830000 945.460000 ;
        RECT 2071.400000 952.020000 2559.740000 953.820000 ;
        RECT 1063.400000 1723.340000 1761.180000 1725.140000 ;
        RECT 766.400000 2473.340000 1464.180000 2475.140000 ;
        RECT 766.400000 1796.400000 1464.180000 1798.200000 ;
        RECT 16.740000 2529.600000 2589.160000 2532.960000 ;
        RECT 0.000000 2578.560000 2605.900000 2586.720000 ;
        RECT 33.400000 1746.400000 731.180000 1748.200000 ;
        RECT 33.400000 2423.340000 731.180000 2425.140000 ;
        RECT 16.740000 2475.200000 761.200000 2478.560000 ;
        RECT 41.760000 2415.910000 43.500000 2424.160000 ;
        RECT 1454.080000 1796.400000 1455.820000 1805.630000 ;
        RECT 1796.400000 1723.340000 2494.180000 1725.140000 ;
        RECT 1469.380000 2475.200000 2589.160000 2478.560000 ;
        RECT 16.740000 1006.400000 2589.160000 1009.760000 ;
        RECT 16.740000 1060.800000 2589.160000 1064.160000 ;
        RECT 16.740000 1115.200000 2589.160000 1118.560000 ;
        RECT 16.740000 1169.600000 2589.160000 1172.960000 ;
        RECT 16.740000 1224.000000 2589.160000 1227.360000 ;
        RECT 16.740000 1278.400000 2589.160000 1281.760000 ;
        RECT 16.740000 1332.800000 2589.160000 1336.160000 ;
        RECT 16.740000 1387.200000 2589.160000 1390.560000 ;
        RECT 16.740000 1441.600000 2589.160000 1444.960000 ;
        RECT 16.740000 1496.000000 2589.160000 1499.360000 ;
        RECT 16.740000 1550.400000 2589.160000 1553.760000 ;
        RECT 16.740000 1604.800000 2589.160000 1608.160000 ;
        RECT 16.740000 1659.200000 2589.160000 1662.560000 ;
        RECT 16.740000 1713.600000 2589.160000 1716.960000 ;
        RECT 16.740000 1768.000000 2589.160000 1771.360000 ;
        RECT 16.740000 1822.400000 2589.160000 1825.760000 ;
        RECT 16.740000 1876.800000 2589.160000 1880.160000 ;
        RECT 16.740000 1931.200000 2589.160000 1934.560000 ;
        RECT 16.740000 1985.600000 2589.160000 1988.960000 ;
        RECT 16.740000 2040.000000 2589.160000 2043.360000 ;
        RECT 16.740000 2094.400000 2589.160000 2097.760000 ;
        RECT 16.740000 2148.800000 2589.160000 2152.160000 ;
        RECT 16.740000 2203.200000 2589.160000 2206.560000 ;
        RECT 16.740000 2257.600000 2589.160000 2260.960000 ;
        RECT 16.740000 2312.000000 2589.160000 2315.360000 ;
        RECT 16.740000 2366.400000 2589.160000 2369.760000 ;
        RECT 16.740000 2420.800000 2589.160000 2424.160000 ;
        RECT 16.740000 190.400000 2589.160000 193.760000 ;
        RECT 16.740000 244.800000 2589.160000 248.160000 ;
        RECT 16.740000 299.200000 2589.160000 302.560000 ;
        RECT 16.740000 353.600000 2589.160000 356.960000 ;
        RECT 16.740000 408.000000 2589.160000 411.360000 ;
        RECT 16.740000 462.400000 2589.160000 465.760000 ;
        RECT 16.740000 516.800000 2589.160000 520.160000 ;
        RECT 16.740000 571.200000 2589.160000 574.560000 ;
        RECT 16.740000 625.600000 2589.160000 628.960000 ;
        RECT 16.740000 680.000000 2589.160000 683.360000 ;
        RECT 16.740000 734.400000 2589.160000 737.760000 ;
        RECT 16.740000 788.800000 2589.160000 792.160000 ;
        RECT 16.740000 843.200000 2589.160000 846.560000 ;
        RECT 16.740000 897.600000 2589.160000 900.960000 ;
        RECT 54.760000 483.720000 56.500000 485.460000 ;
        RECT 1049.640000 94.760000 1051.380000 96.500000 ;
        RECT 54.760000 943.720000 56.500000 945.460000 ;
        RECT 1049.640000 943.720000 1051.380000 945.460000 ;
        RECT 2079.760000 94.760000 2081.500000 96.500000 ;
        RECT 1999.640000 483.720000 2001.380000 485.460000 ;
        RECT 2079.760000 943.720000 2081.500000 945.460000 ;
        RECT 1999.640000 943.720000 2001.380000 945.460000 ;
        RECT 41.760000 2415.040000 43.500000 2416.780000 ;
        RECT 33.400000 2420.800000 35.200000 2425.140000 ;
        RECT 729.380000 2420.800000 731.180000 2425.140000 ;
        RECT 1454.080000 1804.760000 1455.820000 1806.500000 ;
    END
# end of P/G power stripe data as pin

  END VDD
  OBS
    LAYER li1 ;
      RECT 0.000000 0.000000 2605.900000 2603.040000 ;
    LAYER met1 ;
      RECT 0.000000 0.000000 2605.900000 2603.040000 ;
    LAYER met2 ;
      RECT 0.000000 0.000000 2605.900000 2603.040000 ;
    LAYER met3 ;
      RECT 0.000000 0.000000 2605.900000 2603.040000 ;
    LAYER met4 ;
      RECT 0.000000 0.000000 2605.900000 2603.040000 ;
    LAYER met5 ;
      RECT 0.000000 0.000000 2605.900000 2603.040000 ;
  END
END conv

END LIBRARY
